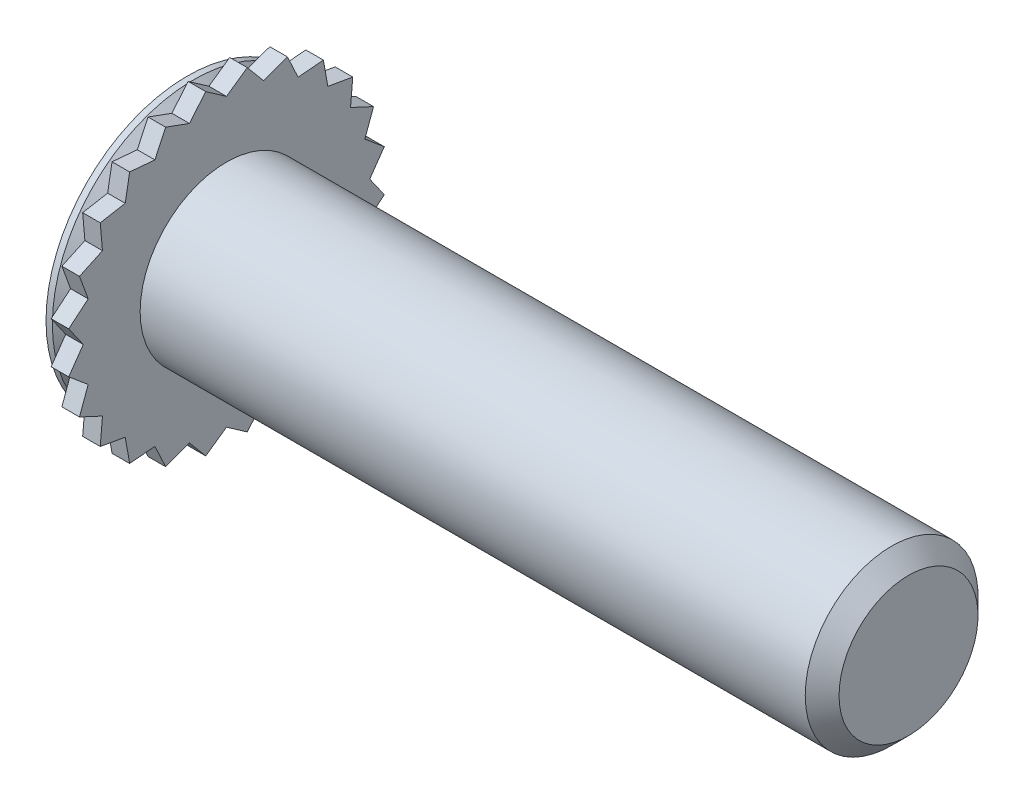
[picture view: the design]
ISO-10303-21;
HEADER;
FILE_DESCRIPTION(('STEP AP214'),'2;1');
FILE_NAME('part.step','',(''),(''),'','','');
FILE_SCHEMA(('AUTOMOTIVE_DESIGN { 1 0 10303 214 1 1 1 1 }'));
ENDSEC;
DATA;
#1=APPLICATION_CONTEXT('core data for automotive mechanical design processes');
#2=APPLICATION_PROTOCOL_DEFINITION('international standard','automotive_design',2000,#1);
#3=PRODUCT_CONTEXT('',#1,'mechanical');
#4=PRODUCT('Part','Part','',(#3));
#5=PRODUCT_RELATED_PRODUCT_CATEGORY('part','',(#4));
#6=PRODUCT_DEFINITION_FORMATION('','',#4);
#7=PRODUCT_DEFINITION_CONTEXT('part definition',#1,'design');
#8=PRODUCT_DEFINITION('design','',#6,#7);
#9=PRODUCT_DEFINITION_SHAPE('','',#8);
#10=(LENGTH_UNIT() NAMED_UNIT(*) SI_UNIT(.MILLI.,.METRE.));
#11=(NAMED_UNIT(*) PLANE_ANGLE_UNIT() SI_UNIT($,.RADIAN.));
#12=(NAMED_UNIT(*) SI_UNIT($,.STERADIAN.) SOLID_ANGLE_UNIT());
#13=UNCERTAINTY_MEASURE_WITH_UNIT(LENGTH_MEASURE(1.E-05),#10,'distance_accuracy_value','');
#14=(GEOMETRIC_REPRESENTATION_CONTEXT(3) GLOBAL_UNCERTAINTY_ASSIGNED_CONTEXT((#13)) GLOBAL_UNIT_ASSIGNED_CONTEXT((#10,
#11,#12)) REPRESENTATION_CONTEXT('',''));
#15=CARTESIAN_POINT('',(0.,0.,0.));
#16=DIRECTION('',(0.,0.,1.));
#17=DIRECTION('',(1.,0.,0.));
#18=AXIS2_PLACEMENT_3D('',#15,#16,#17);
#19=CARTESIAN_POINT('',(1.0922,4.445,0.));
#20=DIRECTION('',(1.,0.,0.));
#21=DIRECTION('',(0.,0.,-1.));
#22=AXIS2_PLACEMENT_3D('',#19,#20,#21);
#23=PLANE('',#22);
#24=DIRECTION('',(0.,0.34225891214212,-0.939605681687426));
#25=VECTOR('',#24,1.);
#26=CARTESIAN_POINT('',(1.0922,4.10664452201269,-1.70102785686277));
#27=LINE('',#26,#25);
#28=CARTESIAN_POINT('',(1.0922,3.86418626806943,-1.03540558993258));
#29=VERTEX_POINT('',#28);
#30=CARTESIAN_POINT('',(1.0922,4.10664452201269,-1.70102785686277));
#31=VERTEX_POINT('',#30);
#32=EDGE_CURVE('E825',#29,#31,#27,.T.);
#33=ORIENTED_EDGE('',*,*,#32,.F.);
#34=DIRECTION('',(0.,-0.766207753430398,-0.642592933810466));
#35=VECTOR('',#34,1.);
#36=CARTESIAN_POINT('',(1.0922,3.86418626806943,-1.03540558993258));
#37=LINE('',#36,#35);
#38=CARTESIAN_POINT('',(1.0922,4.40697240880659,-0.580188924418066));
#39=VERTEX_POINT('',#38);
#40=EDGE_CURVE('E814',#39,#29,#37,.T.);
#41=ORIENTED_EDGE('',*,*,#40,.F.);
#42=DIRECTION('',(0.,0.573784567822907,-0.819006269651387));
#43=VECTOR('',#42,1.);
#44=CARTESIAN_POINT('',(1.0922,4.40697240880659,-0.580188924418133));
#45=LINE('',#44,#43);
#46=CARTESIAN_POINT('',(1.0922,4.0005,0.));
#47=VERTEX_POINT('',#46);
#48=EDGE_CURVE('E198',#47,#39,#45,.T.);
#49=ORIENTED_EDGE('',*,*,#48,.F.);
#50=DIRECTION('',(0.,-0.573784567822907,-0.819006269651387));
#51=VECTOR('',#50,1.);
#52=CARTESIAN_POINT('',(1.0922,4.0005,0.));
#53=LINE('',#52,#51);
#54=CARTESIAN_POINT('',(1.0922,4.40697240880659,0.580188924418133));
#55=VERTEX_POINT('',#54);
#56=EDGE_CURVE('E192',#55,#47,#53,.T.);
#57=ORIENTED_EDGE('',*,*,#56,.F.);
#58=DIRECTION('',(0.,0.766207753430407,-0.642592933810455));
#59=VECTOR('',#58,1.);
#60=CARTESIAN_POINT('',(1.0922,4.40697240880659,0.580188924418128));
#61=LINE('',#60,#59);
#62=CARTESIAN_POINT('',(1.0922,3.86418626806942,1.03540558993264));
#63=VERTEX_POINT('',#62);
#64=EDGE_CURVE('E60',#63,#55,#61,.T.);
#65=ORIENTED_EDGE('',*,*,#64,.F.);
#66=DIRECTION('',(0.,-0.342258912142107,-0.939605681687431));
#67=VECTOR('',#66,1.);
#68=CARTESIAN_POINT('',(1.0922,3.86418626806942,1.03540558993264));
#69=LINE('',#68,#67);
#70=CARTESIAN_POINT('',(1.0922,4.10664452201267,1.70102785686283));
#71=VERTEX_POINT('',#70);
#72=EDGE_CURVE('E177',#71,#63,#69,.T.);
#73=ORIENTED_EDGE('',*,*,#72,.F.);
#74=DIRECTION('',(0.,0.906415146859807,-0.422387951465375));
#75=VECTOR('',#74,1.);
#76=CARTESIAN_POINT('',(1.0922,4.10664452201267,1.70102785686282));
#77=LINE('',#76,#75);
#78=CARTESIAN_POINT('',(1.0922,3.46453462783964,2.00025));
#79=VERTEX_POINT('',#78);
#80=EDGE_CURVE('E77',#79,#71,#77,.T.);
#81=ORIENTED_EDGE('',*,*,#80,.F.);
#82=DIRECTION('',(0.,-0.087408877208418,-0.996172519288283));
#83=VECTOR('',#82,1.);
#84=CARTESIAN_POINT('',(1.0922,3.46453462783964,2.00025));
#85=LINE('',#84,#83);
#86=CARTESIAN_POINT('',(1.0922,3.52645559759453,2.70594455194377));
#87=VERTEX_POINT('',#86);
#88=EDGE_CURVE('E174',#87,#79,#85,.T.);
#89=ORIENTED_EDGE('',*,*,#88,.F.);
#90=DIRECTION('',(0.,0.984851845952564,-0.173397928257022));
#91=VECTOR('',#90,1.);
#92=CARTESIAN_POINT('',(1.0922,3.52645559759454,2.70594455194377));
#93=LINE('',#92,#91);
#94=CARTESIAN_POINT('',(1.0922,2.82878067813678,2.82878067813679));
#95=VERTEX_POINT('',#94);
#96=EDGE_CURVE('E164',#95,#87,#93,.T.);
#97=ORIENTED_EDGE('',*,*,#96,.F.);
#98=DIRECTION('',(0.,0.173397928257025,-0.984851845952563));
#99=VECTOR('',#98,1.);
#100=CARTESIAN_POINT('',(1.0922,2.82878067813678,2.82878067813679));
#101=LINE('',#100,#99);
#102=CARTESIAN_POINT('',(1.0922,2.70594455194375,3.52645559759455));
#103=VERTEX_POINT('',#102);
#104=EDGE_CURVE('E137',#103,#95,#101,.T.);
#105=ORIENTED_EDGE('',*,*,#104,.F.);
#106=DIRECTION('',(0.,0.996172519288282,0.0874088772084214));
#107=VECTOR('',#106,1.);
#108=CARTESIAN_POINT('',(1.0922,2.70594455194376,3.52645559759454));
#109=LINE('',#108,#107);
#110=CARTESIAN_POINT('',(1.0922,2.00024999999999,3.46453462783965));
#111=VERTEX_POINT('',#110);
#112=EDGE_CURVE('E114',#111,#103,#109,.T.);
#113=ORIENTED_EDGE('',*,*,#112,.F.);
#114=DIRECTION('',(0.,0.422387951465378,-0.906415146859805));
#115=VECTOR('',#114,1.);
#116=CARTESIAN_POINT('',(1.0922,2.00024999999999,3.46453462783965));
#117=LINE('',#116,#115);
#118=CARTESIAN_POINT('',(1.0922,1.70102785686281,4.10664452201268));
#119=VERTEX_POINT('',#118);
#120=EDGE_CURVE('E142',#119,#111,#117,.T.);
#121=ORIENTED_EDGE('',*,*,#120,.F.);
#122=DIRECTION('',(0.,0.93960568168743,0.34225891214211));
#123=VECTOR('',#122,1.);
#124=CARTESIAN_POINT('',(1.0922,1.70102785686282,4.10664452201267));
#125=LINE('',#124,#123);
#126=CARTESIAN_POINT('',(1.0922,1.03540558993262,3.86418626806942));
#127=VERTEX_POINT('',#126);
#128=EDGE_CURVE('E1151',#127,#119,#125,.T.);
#129=ORIENTED_EDGE('',*,*,#128,.F.);
#130=DIRECTION('',(0.,0.642592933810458,-0.766207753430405));
#131=VECTOR('',#130,1.);
#132=CARTESIAN_POINT('',(1.0922,1.03540558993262,3.86418626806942));
#133=LINE('',#132,#131);
#134=CARTESIAN_POINT('',(1.0922,0.580188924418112,4.40697240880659));
#135=VERTEX_POINT('',#134);
#136=EDGE_CURVE('E1144',#135,#127,#133,.T.);
#137=ORIENTED_EDGE('',*,*,#136,.F.);
#138=DIRECTION('',(0.,0.819006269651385,0.57378456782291));
#139=VECTOR('',#138,1.);
#140=CARTESIAN_POINT('',(1.0922,0.580188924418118,4.40697240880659));
#141=LINE('',#140,#139);
#142=CARTESIAN_POINT('',(1.0922,0.,4.0005));
#143=VERTEX_POINT('',#142);
#144=EDGE_CURVE('E1133',#143,#135,#141,.T.);
#145=ORIENTED_EDGE('',*,*,#144,.F.);
#146=DIRECTION('',(0.,0.819006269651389,-0.573784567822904));
#147=VECTOR('',#146,1.);
#148=CARTESIAN_POINT('',(1.0922,0.,4.0005));
#149=LINE('',#148,#147);
#150=CARTESIAN_POINT('',(1.0922,-0.580188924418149,4.40697240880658));
#151=VERTEX_POINT('',#150);
#152=EDGE_CURVE('E1126',#151,#143,#149,.T.);
#153=ORIENTED_EDGE('',*,*,#152,.F.);
#154=DIRECTION('',(0.,0.642592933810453,0.76620775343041));
#155=VECTOR('',#154,1.);
#156=CARTESIAN_POINT('',(1.0922,-0.580188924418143,4.40697240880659));
#157=LINE('',#156,#155);
#158=CARTESIAN_POINT('',(1.0922,-1.03540558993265,3.86418626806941));
#159=VERTEX_POINT('',#158);
#160=EDGE_CURVE('E1115',#159,#151,#157,.T.);
#161=ORIENTED_EDGE('',*,*,#160,.F.);
#162=DIRECTION('',(0.,0.939605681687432,-0.342258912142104));
#163=VECTOR('',#162,1.);
#164=CARTESIAN_POINT('',(1.0922,-1.03540558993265,3.86418626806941));
#165=LINE('',#164,#163);
#166=CARTESIAN_POINT('',(1.0922,-1.70102785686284,4.10664452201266));
#167=VERTEX_POINT('',#166);
#168=EDGE_CURVE('E1108',#167,#159,#165,.T.);
#169=ORIENTED_EDGE('',*,*,#168,.F.);
#170=DIRECTION('',(0.,0.422387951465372,0.906415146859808));
#171=VECTOR('',#170,1.);
#172=CARTESIAN_POINT('',(1.0922,-1.70102785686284,4.10664452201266));
#173=LINE('',#172,#171);
#174=CARTESIAN_POINT('',(1.0922,-2.00025000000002,3.46453462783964));
#175=VERTEX_POINT('',#174);
#176=EDGE_CURVE('E1097',#175,#167,#173,.T.);
#177=ORIENTED_EDGE('',*,*,#176,.F.);
#178=DIRECTION('',(0.,0.996172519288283,-0.0874088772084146));
#179=VECTOR('',#178,1.);
#180=CARTESIAN_POINT('',(1.0922,-2.00025000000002,3.46453462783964));
#181=LINE('',#180,#179);
#182=CARTESIAN_POINT('',(1.0922,-2.70594455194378,3.52645559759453));
#183=VERTEX_POINT('',#182);
#184=EDGE_CURVE('E1090',#183,#175,#181,.T.);
#185=ORIENTED_EDGE('',*,*,#184,.F.);
#186=DIRECTION('',(0.,0.173397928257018,0.984851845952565));
#187=VECTOR('',#186,1.);
#188=CARTESIAN_POINT('',(1.0922,-2.70594455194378,3.52645559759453));
#189=LINE('',#188,#187);
#190=CARTESIAN_POINT('',(1.0922,-2.8287806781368,2.82878067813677));
#191=VERTEX_POINT('',#190);
#192=EDGE_CURVE('E1079',#191,#183,#189,.T.);
#193=ORIENTED_EDGE('',*,*,#192,.F.);
#194=DIRECTION('',(0.,0.984851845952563,0.173397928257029));
#195=VECTOR('',#194,1.);
#196=CARTESIAN_POINT('',(1.0922,-2.8287806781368,2.82878067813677));
#197=LINE('',#196,#195);
#198=CARTESIAN_POINT('',(1.0922,-3.52645559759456,2.70594455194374));
#199=VERTEX_POINT('',#198);
#200=EDGE_CURVE('E1072',#199,#191,#197,.T.);
#201=ORIENTED_EDGE('',*,*,#200,.F.);
#202=DIRECTION('',(0.,-0.087408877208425,0.996172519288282));
#203=VECTOR('',#202,1.);
#204=CARTESIAN_POINT('',(1.0922,-3.52645559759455,2.70594455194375));
#205=LINE('',#204,#203);
#206=CARTESIAN_POINT('',(1.0922,-3.46453462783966,2.00024999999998));
#207=VERTEX_POINT('',#206);
#208=EDGE_CURVE('E1061',#207,#199,#205,.T.);
#209=ORIENTED_EDGE('',*,*,#208,.F.);
#210=DIRECTION('',(0.,0.906415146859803,0.422387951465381));
#211=VECTOR('',#210,1.);
#212=CARTESIAN_POINT('',(1.0922,-3.46453462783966,2.00024999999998));
#213=LINE('',#212,#211);
#214=CARTESIAN_POINT('',(1.0922,-4.10664452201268,1.7010278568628));
#215=VERTEX_POINT('',#214);
#216=EDGE_CURVE('E1054',#215,#207,#213,.T.);
#217=ORIENTED_EDGE('',*,*,#216,.F.);
#218=DIRECTION('',(0.,-0.342258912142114,0.939605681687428));
#219=VECTOR('',#218,1.);
#220=CARTESIAN_POINT('',(1.0922,-4.10664452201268,1.7010278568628));
#221=LINE('',#220,#219);
#222=CARTESIAN_POINT('',(1.0922,-3.86418626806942,1.03540558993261));
#223=VERTEX_POINT('',#222);
#224=EDGE_CURVE('E1043',#223,#215,#221,.T.);
#225=ORIENTED_EDGE('',*,*,#224,.F.);
#226=DIRECTION('',(0.,0.766207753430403,0.642592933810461));
#227=VECTOR('',#226,1.);
#228=CARTESIAN_POINT('',(1.0922,-3.86418626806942,1.03540558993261));
#229=LINE('',#228,#227);
#230=CARTESIAN_POINT('',(1.0922,-4.40697240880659,0.580188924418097));
#231=VERTEX_POINT('',#230);
#232=EDGE_CURVE('E1036',#231,#223,#229,.T.);
#233=ORIENTED_EDGE('',*,*,#232,.F.);
#234=DIRECTION('',(0.,-0.573784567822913,0.819006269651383));
#235=VECTOR('',#234,1.);
#236=CARTESIAN_POINT('',(1.0922,-4.40697240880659,0.580188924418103));
#237=LINE('',#236,#235);
#238=CARTESIAN_POINT('',(1.0922,-4.0005,0.));
#239=VERTEX_POINT('',#238);
#240=EDGE_CURVE('E1025',#239,#231,#237,.T.);
#241=ORIENTED_EDGE('',*,*,#240,.F.);
#242=DIRECTION('',(0.,0.573784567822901,0.819006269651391));
#243=VECTOR('',#242,1.);
#244=CARTESIAN_POINT('',(1.0922,-4.0005,0.));
#245=LINE('',#244,#243);
#246=CARTESIAN_POINT('',(1.0922,-4.40697240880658,-0.580188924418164));
#247=VERTEX_POINT('',#246);
#248=EDGE_CURVE('E1018',#247,#239,#245,.T.);
#249=ORIENTED_EDGE('',*,*,#248,.F.);
#250=DIRECTION('',(0.,-0.766207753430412,0.64259293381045));
#251=VECTOR('',#250,1.);
#252=CARTESIAN_POINT('',(1.0922,-4.40697240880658,-0.580188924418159));
#253=LINE('',#252,#251);
#254=CARTESIAN_POINT('',(1.0922,-3.86418626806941,-1.03540558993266));
#255=VERTEX_POINT('',#254);
#256=EDGE_CURVE('E1007',#255,#247,#253,.T.);
#257=ORIENTED_EDGE('',*,*,#256,.F.);
#258=DIRECTION('',(0.,0.342258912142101,0.939605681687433));
#259=VECTOR('',#258,1.);
#260=CARTESIAN_POINT('',(1.0922,-3.86418626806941,-1.03540558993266));
#261=LINE('',#260,#259);
#262=CARTESIAN_POINT('',(1.0922,-4.10664452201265,-1.70102785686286));
#263=VERTEX_POINT('',#262);
#264=EDGE_CURVE('E1000',#263,#255,#261,.T.);
#265=ORIENTED_EDGE('',*,*,#264,.F.);
#266=DIRECTION('',(0.,-0.906415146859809,0.422387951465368));
#267=VECTOR('',#266,1.);
#268=CARTESIAN_POINT('',(1.0922,-4.10664452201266,-1.70102785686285));
#269=LINE('',#268,#267);
#270=CARTESIAN_POINT('',(1.0922,-3.46453462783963,-2.00025000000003));
#271=VERTEX_POINT('',#270);
#272=EDGE_CURVE('E989',#271,#263,#269,.T.);
#273=ORIENTED_EDGE('',*,*,#272,.F.);
#274=DIRECTION('',(0.,0.087408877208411,0.996172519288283));
#275=VECTOR('',#274,1.);
#276=CARTESIAN_POINT('',(1.0922,-3.46453462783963,-2.00025000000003));
#277=LINE('',#276,#275);
#278=CARTESIAN_POINT('',(1.0922,-3.52645559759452,-2.70594455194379));
#279=VERTEX_POINT('',#278);
#280=EDGE_CURVE('E982',#279,#271,#277,.T.);
#281=ORIENTED_EDGE('',*,*,#280,.F.);
#282=DIRECTION('',(0.,-0.984851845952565,0.173397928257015));
#283=VECTOR('',#282,1.);
#284=CARTESIAN_POINT('',(1.0922,-3.52645559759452,-2.70594455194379));
#285=LINE('',#284,#283);
#286=CARTESIAN_POINT('',(1.0922,-2.82878067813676,-2.82878067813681));
#287=VERTEX_POINT('',#286);
#288=EDGE_CURVE('E971',#287,#279,#285,.T.);
#289=ORIENTED_EDGE('',*,*,#288,.F.);
#290=DIRECTION('',(0.,-0.173397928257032,0.984851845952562));
#291=VECTOR('',#290,1.);
#292=CARTESIAN_POINT('',(1.0922,-2.82878067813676,-2.82878067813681));
#293=LINE('',#292,#291);
#294=CARTESIAN_POINT('',(1.0922,-2.70594455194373,-3.52645559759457));
#295=VERTEX_POINT('',#294);
#296=EDGE_CURVE('E964',#295,#287,#293,.T.);
#297=ORIENTED_EDGE('',*,*,#296,.F.);
#298=DIRECTION('',(0.,-0.996172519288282,-0.0874088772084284));
#299=VECTOR('',#298,1.);
#300=CARTESIAN_POINT('',(1.0922,-2.70594455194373,-3.52645559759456));
#301=LINE('',#300,#299);
#302=CARTESIAN_POINT('',(1.0922,-2.00024999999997,-3.46453462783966));
#303=VERTEX_POINT('',#302);
#304=EDGE_CURVE('E953',#303,#295,#301,.T.);
#305=ORIENTED_EDGE('',*,*,#304,.F.);
#306=DIRECTION('',(0.,-0.422387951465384,0.906415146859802));
#307=VECTOR('',#306,1.);
#308=CARTESIAN_POINT('',(1.0922,-2.00024999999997,-3.46453462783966));
#309=LINE('',#308,#307);
#310=CARTESIAN_POINT('',(1.0922,-1.70102785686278,-4.10664452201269));
#311=VERTEX_POINT('',#310);
#312=EDGE_CURVE('E946',#311,#303,#309,.T.);
#313=ORIENTED_EDGE('',*,*,#312,.F.);
#314=DIRECTION('',(0.,-0.939605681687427,-0.342258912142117));
#315=VECTOR('',#314,1.);
#316=CARTESIAN_POINT('',(1.0922,-1.70102785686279,-4.10664452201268));
#317=LINE('',#316,#315);
#318=CARTESIAN_POINT('',(1.0922,-1.0354055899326,-3.86418626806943));
#319=VERTEX_POINT('',#318);
#320=EDGE_CURVE('E935',#319,#311,#317,.T.);
#321=ORIENTED_EDGE('',*,*,#320,.F.);
#322=DIRECTION('',(0.,-0.642592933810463,0.7662077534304));
#323=VECTOR('',#322,1.);
#324=CARTESIAN_POINT('',(1.0922,-1.0354055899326,-3.86418626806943));
#325=LINE('',#324,#323);
#326=CARTESIAN_POINT('',(1.0922,-0.580188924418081,-4.40697240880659));
#327=VERTEX_POINT('',#326);
#328=EDGE_CURVE('E928',#327,#319,#325,.T.);
#329=ORIENTED_EDGE('',*,*,#328,.F.);
#330=DIRECTION('',(0.,-0.819006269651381,-0.573784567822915));
#331=VECTOR('',#330,1.);
#332=CARTESIAN_POINT('',(1.0922,-0.580188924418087,-4.40697240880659));
#333=LINE('',#332,#331);
#334=CARTESIAN_POINT('',(1.0922,0.,-4.0005));
#335=VERTEX_POINT('',#334);
#336=EDGE_CURVE('E917',#335,#327,#333,.T.);
#337=ORIENTED_EDGE('',*,*,#336,.F.);
#338=DIRECTION('',(0.,-0.819006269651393,0.573784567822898));
#339=VECTOR('',#338,1.);
#340=CARTESIAN_POINT('',(1.0922,0.,-4.0005));
#341=LINE('',#340,#339);
#342=CARTESIAN_POINT('',(1.0922,0.58018892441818,-4.40697240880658));
#343=VERTEX_POINT('',#342);
#344=EDGE_CURVE('E910',#343,#335,#341,.T.);
#345=ORIENTED_EDGE('',*,*,#344,.F.);
#346=DIRECTION('',(0.,-0.642592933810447,-0.766207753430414));
#347=VECTOR('',#346,1.);
#348=CARTESIAN_POINT('',(1.0922,0.580188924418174,-4.40697240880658));
#349=LINE('',#348,#347);
#350=CARTESIAN_POINT('',(1.0922,1.03540558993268,-3.86418626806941));
#351=VERTEX_POINT('',#350);
#352=EDGE_CURVE('E899',#351,#343,#349,.T.);
#353=ORIENTED_EDGE('',*,*,#352,.F.);
#354=DIRECTION('',(0.,-0.939605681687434,0.342258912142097));
#355=VECTOR('',#354,1.);
#356=CARTESIAN_POINT('',(1.0922,1.03540558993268,-3.86418626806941));
#357=LINE('',#356,#355);
#358=CARTESIAN_POINT('',(1.0922,1.70102785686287,-4.10664452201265));
#359=VERTEX_POINT('',#358);
#360=EDGE_CURVE('E892',#359,#351,#357,.T.);
#361=ORIENTED_EDGE('',*,*,#360,.F.);
#362=DIRECTION('',(0.,-0.422387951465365,-0.906415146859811));
#363=VECTOR('',#362,1.);
#364=CARTESIAN_POINT('',(1.0922,1.70102785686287,-4.10664452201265));
#365=LINE('',#364,#363);
#366=CARTESIAN_POINT('',(1.0922,2.00025000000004,-3.46453462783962));
#367=VERTEX_POINT('',#366);
#368=EDGE_CURVE('E881',#367,#359,#365,.T.);
#369=ORIENTED_EDGE('',*,*,#368,.F.);
#370=DIRECTION('',(0.,-0.996172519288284,0.0874088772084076));
#371=VECTOR('',#370,1.);
#372=CARTESIAN_POINT('',(1.0922,2.00025000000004,-3.46453462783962));
#373=LINE('',#372,#371);
#374=CARTESIAN_POINT('',(1.0922,2.70594455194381,-3.52645559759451));
#375=VERTEX_POINT('',#374);
#376=EDGE_CURVE('E874',#375,#367,#373,.T.);
#377=ORIENTED_EDGE('',*,*,#376,.F.);
#378=DIRECTION('',(0.,-0.173397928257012,-0.984851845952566));
#379=VECTOR('',#378,1.);
#380=CARTESIAN_POINT('',(1.0922,2.7059445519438,-3.52645559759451));
#381=LINE('',#380,#379);
#382=CARTESIAN_POINT('',(1.0922,2.82878067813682,-2.82878067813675));
#383=VERTEX_POINT('',#382);
#384=EDGE_CURVE('E863',#383,#375,#381,.T.);
#385=ORIENTED_EDGE('',*,*,#384,.F.);
#386=DIRECTION('',(0.,-0.984851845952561,-0.173397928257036));
#387=VECTOR('',#386,1.);
#388=CARTESIAN_POINT('',(1.0922,2.82878067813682,-2.82878067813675));
#389=LINE('',#388,#387);
#390=CARTESIAN_POINT('',(1.0922,3.52645559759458,-2.70594455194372));
#391=VERTEX_POINT('',#390);
#392=EDGE_CURVE('E857',#391,#383,#389,.T.);
#393=ORIENTED_EDGE('',*,*,#392,.F.);
#394=DIRECTION('',(0.,0.0874088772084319,-0.996172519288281));
#395=VECTOR('',#394,1.);
#396=CARTESIAN_POINT('',(1.0922,3.52645559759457,-2.70594455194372));
#397=LINE('',#396,#395);
#398=CARTESIAN_POINT('',(1.0922,3.46453462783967,-2.00024999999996));
#399=VERTEX_POINT('',#398);
#400=EDGE_CURVE('E847',#399,#391,#397,.T.);
#401=ORIENTED_EDGE('',*,*,#400,.F.);
#402=DIRECTION('',(0.,-0.906415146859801,-0.422387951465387));
#403=VECTOR('',#402,1.);
#404=CARTESIAN_POINT('',(1.0922,3.46453462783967,-2.00024999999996));
#405=LINE('',#404,#403);
#406=EDGE_CURVE('E832',#31,#399,#405,.T.);
#407=ORIENTED_EDGE('',*,*,#406,.F.);
#408=EDGE_LOOP('',(#33,#41,#49,#57,#65,#73,#81,#89,#97,#105,#113,#121,#129,#137,#145,#153,#161,
#169,#177,#185,#193,#201,#209,#217,#225,#233,#241,#249,#257,#265,#273,#281,#289,#297,#305,#313,
#321,#329,#337,#345,#353,#361,#369,#377,#385,#393,#401,#407));
#409=FACE_BOUND('',#408,.T.);
#410=CARTESIAN_POINT('',(1.0922,0.,0.));
#411=DIRECTION('',(-1.,0.,0.));
#412=DIRECTION('',(0.,0.,1.));
#413=AXIS2_PLACEMENT_3D('',#410,#411,#412);
#414=CIRCLE('',#413,2.413);
#415=CARTESIAN_POINT('',(1.0922,0.,2.413));
#416=VERTEX_POINT('',#415);
#417=EDGE_CURVE('E11',#416,#416,#414,.T.);
#418=ORIENTED_EDGE('',*,*,#417,.T.);
#419=EDGE_LOOP('',(#418));
#420=FACE_BOUND('',#419,.T.);
#421=ADVANCED_FACE('F33',(#409,#420),#23,.T.);
#422=CARTESIAN_POINT('',(0.,0.,0.));
#423=DIRECTION('',(-1.,0.,0.));
#424=DIRECTION('',(0.,0.,1.));
#425=AXIS2_PLACEMENT_3D('',#422,#423,#424);
#426=CYLINDRICAL_SURFACE('',#425,2.413);
#427=CARTESIAN_POINT('',(19.6697599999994,0.,0.));
#428=DIRECTION('',(-1.,0.,0.));
#429=DIRECTION('',(0.,0.,1.));
#430=AXIS2_PLACEMENT_3D('',#427,#428,#429);
#431=CIRCLE('',#430,2.413);
#432=CARTESIAN_POINT('',(19.6697599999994,0.,2.413));
#433=VERTEX_POINT('',#432);
#434=EDGE_CURVE('E41',#433,#433,#431,.T.);
#435=ORIENTED_EDGE('',*,*,#434,.T.);
#436=EDGE_LOOP('',(#435));
#437=FACE_BOUND('',#436,.T.);
#438=ORIENTED_EDGE('',*,*,#417,.F.);
#439=EDGE_LOOP('',(#438));
#440=FACE_BOUND('',#439,.T.);
#441=ADVANCED_FACE('F232',(#437,#440),#426,.T.);
#442=CARTESIAN_POINT('',(20.1422,0.,0.));
#443=DIRECTION('',(-1.,0.,0.));
#444=DIRECTION('',(0.,0.,1.));
#445=AXIS2_PLACEMENT_3D('',#442,#443,#444);
#446=CONICAL_SURFACE('',#445,1.94056,0.785398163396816);
#447=ORIENTED_EDGE('',*,*,#434,.F.);
#448=EDGE_LOOP('',(#447));
#449=FACE_BOUND('',#448,.T.);
#450=CARTESIAN_POINT('',(20.1422,0.,0.));
#451=DIRECTION('',(-1.,0.,0.));
#452=DIRECTION('',(0.,0.,1.));
#453=AXIS2_PLACEMENT_3D('',#450,#451,#452);
#454=CIRCLE('',#453,1.94056);
#455=CARTESIAN_POINT('',(20.1422,0.,1.94056));
#456=VERTEX_POINT('',#455);
#457=EDGE_CURVE('E227',#456,#456,#454,.T.);
#458=ORIENTED_EDGE('',*,*,#457,.T.);
#459=EDGE_LOOP('',(#458));
#460=FACE_BOUND('',#459,.T.);
#461=ADVANCED_FACE('F235',(#449,#460),#446,.T.);
#462=CARTESIAN_POINT('',(20.1422,1.94056,0.));
#463=DIRECTION('',(1.,0.,0.));
#464=DIRECTION('',(0.,0.,-1.));
#465=AXIS2_PLACEMENT_3D('',#462,#463,#464);
#466=PLANE('',#465);
#467=ORIENTED_EDGE('',*,*,#457,.F.);
#468=EDGE_LOOP('',(#467));
#469=FACE_BOUND('',#468,.T.);
#470=ADVANCED_FACE('F238',(#469),#466,.T.);
#471=CARTESIAN_POINT('',(0.5461,1.6764,0.));
#472=DIRECTION('',(1.,0.,0.));
#473=DIRECTION('',(0.,0.,-1.));
#474=AXIS2_PLACEMENT_3D('',#471,#472,#473);
#475=PLANE('',#474);
#476=CARTESIAN_POINT('',(0.5461,0.,0.));
#477=DIRECTION('',(-1.,0.,0.));
#478=DIRECTION('',(0.,0.,1.));
#479=AXIS2_PLACEMENT_3D('',#476,#477,#478);
#480=CIRCLE('',#479,1.6764);
#481=CARTESIAN_POINT('',(0.5461,0.,1.6764));
#482=VERTEX_POINT('',#481);
#483=EDGE_CURVE('E224',#482,#482,#480,.T.);
#484=ORIENTED_EDGE('',*,*,#483,.T.);
#485=EDGE_LOOP('',(#484));
#486=FACE_BOUND('',#485,.T.);
#487=ADVANCED_FACE('F243',(#486),#475,.F.);
#488=CARTESIAN_POINT('',(0.,0.,0.));
#489=DIRECTION('',(-1.,0.,0.));
#490=DIRECTION('',(0.,0.,1.));
#491=AXIS2_PLACEMENT_3D('',#488,#489,#490);
#492=CONICAL_SURFACE('',#491,2.2225,0.78539816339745);
#493=ORIENTED_EDGE('',*,*,#483,.F.);
#494=EDGE_LOOP('',(#493));
#495=FACE_BOUND('',#494,.T.);
#496=CARTESIAN_POINT('',(0.,0.,0.));
#497=DIRECTION('',(-1.,0.,0.));
#498=DIRECTION('',(0.,0.,1.));
#499=AXIS2_PLACEMENT_3D('',#496,#497,#498);
#500=CIRCLE('',#499,2.2225);
#501=CARTESIAN_POINT('',(0.,0.,2.2225));
#502=VERTEX_POINT('',#501);
#503=EDGE_CURVE('E221',#502,#502,#500,.T.);
#504=ORIENTED_EDGE('',*,*,#503,.T.);
#505=EDGE_LOOP('',(#504));
#506=FACE_BOUND('',#505,.T.);
#507=ADVANCED_FACE('F248',(#495,#506),#492,.F.);
#508=CARTESIAN_POINT('',(0.,2.2225,0.));
#509=DIRECTION('',(-1.,0.,0.));
#510=DIRECTION('',(0.,0.,1.));
#511=AXIS2_PLACEMENT_3D('',#508,#509,#510);
#512=PLANE('',#511);
#513=CARTESIAN_POINT('',(0.,0.,0.));
#514=DIRECTION('',(-1.,0.,0.));
#515=DIRECTION('',(0.,0.,1.));
#516=AXIS2_PLACEMENT_3D('',#513,#514,#515);
#517=CIRCLE('',#516,3.9497);
#518=CARTESIAN_POINT('',(0.,0.,3.9497));
#519=VERTEX_POINT('',#518);
#520=EDGE_CURVE('E218',#519,#519,#517,.T.);
#521=ORIENTED_EDGE('',*,*,#520,.T.);
#522=EDGE_LOOP('',(#521));
#523=FACE_BOUND('',#522,.T.);
#524=ORIENTED_EDGE('',*,*,#503,.F.);
#525=EDGE_LOOP('',(#524));
#526=FACE_BOUND('',#525,.T.);
#527=ADVANCED_FACE('F280',(#523,#526),#512,.T.);
#528=CARTESIAN_POINT('',(0.,0.,0.));
#529=DIRECTION('',(-1.,0.,0.));
#530=DIRECTION('',(0.,0.,1.));
#531=AXIS2_PLACEMENT_3D('',#528,#529,#530);
#532=CYLINDRICAL_SURFACE('',#531,3.9497);
#533=ORIENTED_EDGE('',*,*,#520,.F.);
#534=EDGE_LOOP('',(#533));
#535=FACE_BOUND('',#534,.T.);
#536=CARTESIAN_POINT('',(0.1778,0.,0.));
#537=DIRECTION('',(-1.,0.,0.));
#538=DIRECTION('',(0.,0.,1.));
#539=AXIS2_PLACEMENT_3D('',#536,#537,#538);
#540=CIRCLE('',#539,3.9497);
#541=CARTESIAN_POINT('',(0.1778,0.,3.9497));
#542=VERTEX_POINT('',#541);
#543=EDGE_CURVE('E215',#542,#542,#540,.T.);
#544=ORIENTED_EDGE('',*,*,#543,.T.);
#545=EDGE_LOOP('',(#544));
#546=FACE_BOUND('',#545,.T.);
#547=ADVANCED_FACE('F290',(#535,#546),#532,.T.);
#548=CARTESIAN_POINT('',(0.49149,0.,0.));
#549=DIRECTION('',(-1.,0.,0.));
#550=DIRECTION('',(0.,0.,1.));
#551=AXIS2_PLACEMENT_3D('',#548,#549,#550);
#552=CONICAL_SURFACE('',#551,3.63601,0.785398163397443);
#553=ORIENTED_EDGE('',*,*,#543,.F.);
#554=EDGE_LOOP('',(#553));
#555=FACE_BOUND('',#554,.T.);
#556=CARTESIAN_POINT('',(0.49149,0.,0.));
#557=DIRECTION('',(-1.,0.,0.));
#558=DIRECTION('',(0.,0.,1.));
#559=AXIS2_PLACEMENT_3D('',#556,#557,#558);
#560=CIRCLE('',#559,3.63601);
#561=CARTESIAN_POINT('',(0.49149,0.,3.63601));
#562=VERTEX_POINT('',#561);
#563=EDGE_CURVE('E212',#562,#562,#560,.T.);
#564=ORIENTED_EDGE('',*,*,#563,.T.);
#565=EDGE_LOOP('',(#564));
#566=FACE_BOUND('',#565,.T.);
#567=ADVANCED_FACE('F300',(#555,#566),#552,.T.);
#568=CARTESIAN_POINT('',(0.,0.,0.));
#569=DIRECTION('',(-1.,0.,0.));
#570=DIRECTION('',(0.,0.,1.));
#571=AXIS2_PLACEMENT_3D('',#568,#569,#570);
#572=CYLINDRICAL_SURFACE('',#571,3.63601);
#573=ORIENTED_EDGE('',*,*,#563,.F.);
#574=EDGE_LOOP('',(#573));
#575=FACE_BOUND('',#574,.T.);
#576=CARTESIAN_POINT('',(0.60071,0.,0.));
#577=DIRECTION('',(-1.,0.,0.));
#578=DIRECTION('',(0.,0.,1.));
#579=AXIS2_PLACEMENT_3D('',#576,#577,#578);
#580=CIRCLE('',#579,3.63601);
#581=CARTESIAN_POINT('',(0.60071,0.,3.63601));
#582=VERTEX_POINT('',#581);
#583=EDGE_CURVE('E207',#582,#582,#580,.T.);
#584=ORIENTED_EDGE('',*,*,#583,.T.);
#585=EDGE_LOOP('',(#584));
#586=FACE_BOUND('',#585,.T.);
#587=ADVANCED_FACE('F310',(#575,#586),#572,.T.);
#588=CARTESIAN_POINT('',(0.60071,4.445,0.));
#589=DIRECTION('',(1.,0.,0.));
#590=DIRECTION('',(0.,0.,-1.));
#591=AXIS2_PLACEMENT_3D('',#588,#589,#590);
#592=PLANE('',#591);
#593=ORIENTED_EDGE('',*,*,#583,.F.);
#594=EDGE_LOOP('',(#593));
#595=FACE_BOUND('',#594,.T.);
#596=DIRECTION('',(0.,-0.766207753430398,-0.642592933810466));
#597=VECTOR('',#596,1.);
#598=CARTESIAN_POINT('',(0.60071,3.86418626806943,-1.03540558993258));
#599=LINE('',#598,#597);
#600=CARTESIAN_POINT('',(0.60071,4.40697240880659,-0.580188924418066));
#601=VERTEX_POINT('',#600);
#602=CARTESIAN_POINT('',(0.60071,3.86418626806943,-1.03540558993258));
#603=VERTEX_POINT('',#602);
#604=EDGE_CURVE('E835',#601,#603,#599,.T.);
#605=ORIENTED_EDGE('',*,*,#604,.T.);
#606=DIRECTION('',(0.,0.34225891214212,-0.939605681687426));
#607=VECTOR('',#606,1.);
#608=CARTESIAN_POINT('',(0.60071,4.10664452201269,-1.70102785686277));
#609=LINE('',#608,#607);
#610=CARTESIAN_POINT('',(0.60071,4.10664452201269,-1.70102785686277));
#611=VERTEX_POINT('',#610);
#612=EDGE_CURVE('E838',#603,#611,#609,.T.);
#613=ORIENTED_EDGE('',*,*,#612,.T.);
#614=DIRECTION('',(0.,-0.906415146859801,-0.422387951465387));
#615=VECTOR('',#614,1.);
#616=CARTESIAN_POINT('',(0.60071,3.46453462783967,-2.00024999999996));
#617=LINE('',#616,#615);
#618=CARTESIAN_POINT('',(0.60071,3.46453462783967,-2.00024999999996));
#619=VERTEX_POINT('',#618);
#620=EDGE_CURVE('E843',#611,#619,#617,.T.);
#621=ORIENTED_EDGE('',*,*,#620,.T.);
#622=DIRECTION('',(0.,0.0874088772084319,-0.996172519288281));
#623=VECTOR('',#622,1.);
#624=CARTESIAN_POINT('',(0.60071,3.52645559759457,-2.70594455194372));
#625=LINE('',#624,#623);
#626=CARTESIAN_POINT('',(0.60071,3.52645559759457,-2.70594455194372));
#627=VERTEX_POINT('',#626);
#628=EDGE_CURVE('E846',#619,#627,#625,.T.);
#629=ORIENTED_EDGE('',*,*,#628,.T.);
#630=DIRECTION('',(0.,-0.984851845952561,-0.173397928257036));
#631=VECTOR('',#630,1.);
#632=CARTESIAN_POINT('',(0.60071,2.82878067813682,-2.82878067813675));
#633=LINE('',#632,#631);
#634=CARTESIAN_POINT('',(0.60071,2.82878067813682,-2.82878067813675));
#635=VERTEX_POINT('',#634);
#636=EDGE_CURVE('E859',#627,#635,#633,.T.);
#637=ORIENTED_EDGE('',*,*,#636,.T.);
#638=DIRECTION('',(0.,-0.173397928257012,-0.984851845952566));
#639=VECTOR('',#638,1.);
#640=CARTESIAN_POINT('',(0.60071,2.7059445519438,-3.52645559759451));
#641=LINE('',#640,#639);
#642=CARTESIAN_POINT('',(0.60071,2.7059445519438,-3.52645559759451));
#643=VERTEX_POINT('',#642);
#644=EDGE_CURVE('E862',#635,#643,#641,.T.);
#645=ORIENTED_EDGE('',*,*,#644,.T.);
#646=DIRECTION('',(0.,-0.996172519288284,0.0874088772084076));
#647=VECTOR('',#646,1.);
#648=CARTESIAN_POINT('',(0.60071,2.00025000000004,-3.46453462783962));
#649=LINE('',#648,#647);
#650=CARTESIAN_POINT('',(0.60071,2.00025000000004,-3.46453462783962));
#651=VERTEX_POINT('',#650);
#652=EDGE_CURVE('E877',#643,#651,#649,.T.);
#653=ORIENTED_EDGE('',*,*,#652,.T.);
#654=DIRECTION('',(0.,-0.422387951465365,-0.906415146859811));
#655=VECTOR('',#654,1.);
#656=CARTESIAN_POINT('',(0.60071,1.70102785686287,-4.10664452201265));
#657=LINE('',#656,#655);
#658=CARTESIAN_POINT('',(0.60071,1.70102785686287,-4.10664452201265));
#659=VERTEX_POINT('',#658);
#660=EDGE_CURVE('E880',#651,#659,#657,.T.);
#661=ORIENTED_EDGE('',*,*,#660,.T.);
#662=DIRECTION('',(0.,-0.939605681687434,0.342258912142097));
#663=VECTOR('',#662,1.);
#664=CARTESIAN_POINT('',(0.60071,1.03540558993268,-3.86418626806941));
#665=LINE('',#664,#663);
#666=CARTESIAN_POINT('',(0.60071,1.03540558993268,-3.86418626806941));
#667=VERTEX_POINT('',#666);
#668=EDGE_CURVE('E895',#659,#667,#665,.T.);
#669=ORIENTED_EDGE('',*,*,#668,.T.);
#670=DIRECTION('',(0.,-0.642592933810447,-0.766207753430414));
#671=VECTOR('',#670,1.);
#672=CARTESIAN_POINT('',(0.60071,0.580188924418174,-4.40697240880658));
#673=LINE('',#672,#671);
#674=CARTESIAN_POINT('',(0.60071,0.580188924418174,-4.40697240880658));
#675=VERTEX_POINT('',#674);
#676=EDGE_CURVE('E898',#667,#675,#673,.T.);
#677=ORIENTED_EDGE('',*,*,#676,.T.);
#678=DIRECTION('',(0.,-0.819006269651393,0.573784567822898));
#679=VECTOR('',#678,1.);
#680=CARTESIAN_POINT('',(0.60071,0.,-4.0005));
#681=LINE('',#680,#679);
#682=CARTESIAN_POINT('',(0.60071,0.,-4.0005));
#683=VERTEX_POINT('',#682);
#684=EDGE_CURVE('E913',#675,#683,#681,.T.);
#685=ORIENTED_EDGE('',*,*,#684,.T.);
#686=DIRECTION('',(0.,-0.819006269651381,-0.573784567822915));
#687=VECTOR('',#686,1.);
#688=CARTESIAN_POINT('',(0.60071,-0.580188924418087,-4.40697240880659));
#689=LINE('',#688,#687);
#690=CARTESIAN_POINT('',(0.60071,-0.580188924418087,-4.40697240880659));
#691=VERTEX_POINT('',#690);
#692=EDGE_CURVE('E916',#683,#691,#689,.T.);
#693=ORIENTED_EDGE('',*,*,#692,.T.);
#694=DIRECTION('',(0.,-0.642592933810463,0.7662077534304));
#695=VECTOR('',#694,1.);
#696=CARTESIAN_POINT('',(0.60071,-1.0354055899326,-3.86418626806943));
#697=LINE('',#696,#695);
#698=CARTESIAN_POINT('',(0.60071,-1.0354055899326,-3.86418626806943));
#699=VERTEX_POINT('',#698);
#700=EDGE_CURVE('E931',#691,#699,#697,.T.);
#701=ORIENTED_EDGE('',*,*,#700,.T.);
#702=DIRECTION('',(0.,-0.939605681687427,-0.342258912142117));
#703=VECTOR('',#702,1.);
#704=CARTESIAN_POINT('',(0.60071,-1.70102785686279,-4.10664452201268));
#705=LINE('',#704,#703);
#706=CARTESIAN_POINT('',(0.60071,-1.70102785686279,-4.10664452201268));
#707=VERTEX_POINT('',#706);
#708=EDGE_CURVE('E934',#699,#707,#705,.T.);
#709=ORIENTED_EDGE('',*,*,#708,.T.);
#710=DIRECTION('',(0.,-0.422387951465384,0.906415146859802));
#711=VECTOR('',#710,1.);
#712=CARTESIAN_POINT('',(0.60071,-2.00024999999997,-3.46453462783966));
#713=LINE('',#712,#711);
#714=CARTESIAN_POINT('',(0.60071,-2.00024999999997,-3.46453462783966));
#715=VERTEX_POINT('',#714);
#716=EDGE_CURVE('E949',#707,#715,#713,.T.);
#717=ORIENTED_EDGE('',*,*,#716,.T.);
#718=DIRECTION('',(0.,-0.996172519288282,-0.0874088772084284));
#719=VECTOR('',#718,1.);
#720=CARTESIAN_POINT('',(0.60071,-2.70594455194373,-3.52645559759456));
#721=LINE('',#720,#719);
#722=CARTESIAN_POINT('',(0.60071,-2.70594455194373,-3.52645559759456));
#723=VERTEX_POINT('',#722);
#724=EDGE_CURVE('E952',#715,#723,#721,.T.);
#725=ORIENTED_EDGE('',*,*,#724,.T.);
#726=DIRECTION('',(0.,-0.173397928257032,0.984851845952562));
#727=VECTOR('',#726,1.);
#728=CARTESIAN_POINT('',(0.60071,-2.82878067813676,-2.82878067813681));
#729=LINE('',#728,#727);
#730=CARTESIAN_POINT('',(0.60071,-2.82878067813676,-2.82878067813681));
#731=VERTEX_POINT('',#730);
#732=EDGE_CURVE('E967',#723,#731,#729,.T.);
#733=ORIENTED_EDGE('',*,*,#732,.T.);
#734=DIRECTION('',(0.,-0.984851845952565,0.173397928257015));
#735=VECTOR('',#734,1.);
#736=CARTESIAN_POINT('',(0.60071,-3.52645559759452,-2.70594455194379));
#737=LINE('',#736,#735);
#738=CARTESIAN_POINT('',(0.60071,-3.52645559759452,-2.70594455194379));
#739=VERTEX_POINT('',#738);
#740=EDGE_CURVE('E970',#731,#739,#737,.T.);
#741=ORIENTED_EDGE('',*,*,#740,.T.);
#742=DIRECTION('',(0.,0.087408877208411,0.996172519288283));
#743=VECTOR('',#742,1.);
#744=CARTESIAN_POINT('',(0.60071,-3.46453462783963,-2.00025000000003));
#745=LINE('',#744,#743);
#746=CARTESIAN_POINT('',(0.60071,-3.46453462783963,-2.00025000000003));
#747=VERTEX_POINT('',#746);
#748=EDGE_CURVE('E985',#739,#747,#745,.T.);
#749=ORIENTED_EDGE('',*,*,#748,.T.);
#750=DIRECTION('',(0.,-0.906415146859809,0.422387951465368));
#751=VECTOR('',#750,1.);
#752=CARTESIAN_POINT('',(0.60071,-4.10664452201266,-1.70102785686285));
#753=LINE('',#752,#751);
#754=CARTESIAN_POINT('',(0.60071,-4.10664452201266,-1.70102785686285));
#755=VERTEX_POINT('',#754);
#756=EDGE_CURVE('E988',#747,#755,#753,.T.);
#757=ORIENTED_EDGE('',*,*,#756,.T.);
#758=DIRECTION('',(0.,0.342258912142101,0.939605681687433));
#759=VECTOR('',#758,1.);
#760=CARTESIAN_POINT('',(0.60071,-3.86418626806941,-1.03540558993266));
#761=LINE('',#760,#759);
#762=CARTESIAN_POINT('',(0.60071,-3.86418626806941,-1.03540558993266));
#763=VERTEX_POINT('',#762);
#764=EDGE_CURVE('E1003',#755,#763,#761,.T.);
#765=ORIENTED_EDGE('',*,*,#764,.T.);
#766=DIRECTION('',(0.,-0.766207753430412,0.64259293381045));
#767=VECTOR('',#766,1.);
#768=CARTESIAN_POINT('',(0.60071,-4.40697240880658,-0.580188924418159));
#769=LINE('',#768,#767);
#770=CARTESIAN_POINT('',(0.60071,-4.40697240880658,-0.580188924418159));
#771=VERTEX_POINT('',#770);
#772=EDGE_CURVE('E1006',#763,#771,#769,.T.);
#773=ORIENTED_EDGE('',*,*,#772,.T.);
#774=DIRECTION('',(0.,0.573784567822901,0.819006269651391));
#775=VECTOR('',#774,1.);
#776=CARTESIAN_POINT('',(0.60071,-4.0005,0.));
#777=LINE('',#776,#775);
#778=CARTESIAN_POINT('',(0.60071,-4.0005,0.));
#779=VERTEX_POINT('',#778);
#780=EDGE_CURVE('E1021',#771,#779,#777,.T.);
#781=ORIENTED_EDGE('',*,*,#780,.T.);
#782=DIRECTION('',(0.,-0.573784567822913,0.819006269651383));
#783=VECTOR('',#782,1.);
#784=CARTESIAN_POINT('',(0.60071,-4.40697240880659,0.580188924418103));
#785=LINE('',#784,#783);
#786=CARTESIAN_POINT('',(0.60071,-4.40697240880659,0.580188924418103));
#787=VERTEX_POINT('',#786);
#788=EDGE_CURVE('E1024',#779,#787,#785,.T.);
#789=ORIENTED_EDGE('',*,*,#788,.T.);
#790=DIRECTION('',(0.,0.766207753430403,0.642592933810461));
#791=VECTOR('',#790,1.);
#792=CARTESIAN_POINT('',(0.60071,-3.86418626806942,1.03540558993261));
#793=LINE('',#792,#791);
#794=CARTESIAN_POINT('',(0.60071,-3.86418626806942,1.03540558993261));
#795=VERTEX_POINT('',#794);
#796=EDGE_CURVE('E1039',#787,#795,#793,.T.);
#797=ORIENTED_EDGE('',*,*,#796,.T.);
#798=DIRECTION('',(0.,-0.342258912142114,0.939605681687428));
#799=VECTOR('',#798,1.);
#800=CARTESIAN_POINT('',(0.60071,-4.10664452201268,1.7010278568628));
#801=LINE('',#800,#799);
#802=CARTESIAN_POINT('',(0.60071,-4.10664452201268,1.7010278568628));
#803=VERTEX_POINT('',#802);
#804=EDGE_CURVE('E1042',#795,#803,#801,.T.);
#805=ORIENTED_EDGE('',*,*,#804,.T.);
#806=DIRECTION('',(0.,0.906415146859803,0.422387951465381));
#807=VECTOR('',#806,1.);
#808=CARTESIAN_POINT('',(0.60071,-3.46453462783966,2.00024999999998));
#809=LINE('',#808,#807);
#810=CARTESIAN_POINT('',(0.60071,-3.46453462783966,2.00024999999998));
#811=VERTEX_POINT('',#810);
#812=EDGE_CURVE('E1057',#803,#811,#809,.T.);
#813=ORIENTED_EDGE('',*,*,#812,.T.);
#814=DIRECTION('',(0.,-0.087408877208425,0.996172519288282));
#815=VECTOR('',#814,1.);
#816=CARTESIAN_POINT('',(0.60071,-3.52645559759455,2.70594455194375));
#817=LINE('',#816,#815);
#818=CARTESIAN_POINT('',(0.60071,-3.52645559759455,2.70594455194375));
#819=VERTEX_POINT('',#818);
#820=EDGE_CURVE('E1060',#811,#819,#817,.T.);
#821=ORIENTED_EDGE('',*,*,#820,.T.);
#822=DIRECTION('',(0.,0.984851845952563,0.173397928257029));
#823=VECTOR('',#822,1.);
#824=CARTESIAN_POINT('',(0.60071,-2.8287806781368,2.82878067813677));
#825=LINE('',#824,#823);
#826=CARTESIAN_POINT('',(0.60071,-2.8287806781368,2.82878067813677));
#827=VERTEX_POINT('',#826);
#828=EDGE_CURVE('E1075',#819,#827,#825,.T.);
#829=ORIENTED_EDGE('',*,*,#828,.T.);
#830=DIRECTION('',(0.,0.173397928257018,0.984851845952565));
#831=VECTOR('',#830,1.);
#832=CARTESIAN_POINT('',(0.60071,-2.70594455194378,3.52645559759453));
#833=LINE('',#832,#831);
#834=CARTESIAN_POINT('',(0.60071,-2.70594455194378,3.52645559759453));
#835=VERTEX_POINT('',#834);
#836=EDGE_CURVE('E1078',#827,#835,#833,.T.);
#837=ORIENTED_EDGE('',*,*,#836,.T.);
#838=DIRECTION('',(0.,0.996172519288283,-0.0874088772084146));
#839=VECTOR('',#838,1.);
#840=CARTESIAN_POINT('',(0.60071,-2.00025000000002,3.46453462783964));
#841=LINE('',#840,#839);
#842=CARTESIAN_POINT('',(0.60071,-2.00025000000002,3.46453462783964));
#843=VERTEX_POINT('',#842);
#844=EDGE_CURVE('E1093',#835,#843,#841,.T.);
#845=ORIENTED_EDGE('',*,*,#844,.T.);
#846=DIRECTION('',(0.,0.422387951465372,0.906415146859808));
#847=VECTOR('',#846,1.);
#848=CARTESIAN_POINT('',(0.60071,-1.70102785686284,4.10664452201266));
#849=LINE('',#848,#847);
#850=CARTESIAN_POINT('',(0.60071,-1.70102785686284,4.10664452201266));
#851=VERTEX_POINT('',#850);
#852=EDGE_CURVE('E1096',#843,#851,#849,.T.);
#853=ORIENTED_EDGE('',*,*,#852,.T.);
#854=DIRECTION('',(0.,0.939605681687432,-0.342258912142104));
#855=VECTOR('',#854,1.);
#856=CARTESIAN_POINT('',(0.60071,-1.03540558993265,3.86418626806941));
#857=LINE('',#856,#855);
#858=CARTESIAN_POINT('',(0.60071,-1.03540558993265,3.86418626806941));
#859=VERTEX_POINT('',#858);
#860=EDGE_CURVE('E1111',#851,#859,#857,.T.);
#861=ORIENTED_EDGE('',*,*,#860,.T.);
#862=DIRECTION('',(0.,0.642592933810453,0.76620775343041));
#863=VECTOR('',#862,1.);
#864=CARTESIAN_POINT('',(0.60071,-0.580188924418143,4.40697240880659));
#865=LINE('',#864,#863);
#866=CARTESIAN_POINT('',(0.60071,-0.580188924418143,4.40697240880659));
#867=VERTEX_POINT('',#866);
#868=EDGE_CURVE('E1114',#859,#867,#865,.T.);
#869=ORIENTED_EDGE('',*,*,#868,.T.);
#870=DIRECTION('',(0.,0.819006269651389,-0.573784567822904));
#871=VECTOR('',#870,1.);
#872=CARTESIAN_POINT('',(0.60071,0.,4.0005));
#873=LINE('',#872,#871);
#874=CARTESIAN_POINT('',(0.60071,0.,4.0005));
#875=VERTEX_POINT('',#874);
#876=EDGE_CURVE('E1129',#867,#875,#873,.T.);
#877=ORIENTED_EDGE('',*,*,#876,.T.);
#878=DIRECTION('',(0.,0.819006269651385,0.57378456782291));
#879=VECTOR('',#878,1.);
#880=CARTESIAN_POINT('',(0.60071,0.580188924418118,4.40697240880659));
#881=LINE('',#880,#879);
#882=CARTESIAN_POINT('',(0.60071,0.580188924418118,4.40697240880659));
#883=VERTEX_POINT('',#882);
#884=EDGE_CURVE('E1132',#875,#883,#881,.T.);
#885=ORIENTED_EDGE('',*,*,#884,.T.);
#886=DIRECTION('',(0.,0.642592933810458,-0.766207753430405));
#887=VECTOR('',#886,1.);
#888=CARTESIAN_POINT('',(0.60071,1.03540558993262,3.86418626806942));
#889=LINE('',#888,#887);
#890=CARTESIAN_POINT('',(0.60071,1.03540558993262,3.86418626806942));
#891=VERTEX_POINT('',#890);
#892=EDGE_CURVE('E1147',#883,#891,#889,.T.);
#893=ORIENTED_EDGE('',*,*,#892,.T.);
#894=DIRECTION('',(0.,0.93960568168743,0.34225891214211));
#895=VECTOR('',#894,1.);
#896=CARTESIAN_POINT('',(0.60071,1.70102785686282,4.10664452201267));
#897=LINE('',#896,#895);
#898=CARTESIAN_POINT('',(0.60071,1.70102785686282,4.10664452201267));
#899=VERTEX_POINT('',#898);
#900=EDGE_CURVE('E1150',#891,#899,#897,.T.);
#901=ORIENTED_EDGE('',*,*,#900,.T.);
#902=DIRECTION('',(0.,0.422387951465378,-0.906415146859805));
#903=VECTOR('',#902,1.);
#904=CARTESIAN_POINT('',(0.60071,2.00024999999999,3.46453462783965));
#905=LINE('',#904,#903);
#906=CARTESIAN_POINT('',(0.60071,2.00024999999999,3.46453462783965));
#907=VERTEX_POINT('',#906);
#908=EDGE_CURVE('E154',#899,#907,#905,.T.);
#909=ORIENTED_EDGE('',*,*,#908,.T.);
#910=DIRECTION('',(0.,0.996172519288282,0.0874088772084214));
#911=VECTOR('',#910,1.);
#912=CARTESIAN_POINT('',(0.60071,2.70594455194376,3.52645559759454));
#913=LINE('',#912,#911);
#914=CARTESIAN_POINT('',(0.60071,2.70594455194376,3.52645559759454));
#915=VERTEX_POINT('',#914);
#916=EDGE_CURVE('E133',#907,#915,#913,.T.);
#917=ORIENTED_EDGE('',*,*,#916,.T.);
#918=DIRECTION('',(0.,0.173397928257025,-0.984851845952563));
#919=VECTOR('',#918,1.);
#920=CARTESIAN_POINT('',(0.60071,2.82878067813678,2.82878067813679));
#921=LINE('',#920,#919);
#922=CARTESIAN_POINT('',(0.60071,2.82878067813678,2.82878067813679));
#923=VERTEX_POINT('',#922);
#924=EDGE_CURVE('E160',#915,#923,#921,.T.);
#925=ORIENTED_EDGE('',*,*,#924,.T.);
#926=DIRECTION('',(0.,0.984851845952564,-0.173397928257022));
#927=VECTOR('',#926,1.);
#928=CARTESIAN_POINT('',(0.60071,3.52645559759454,2.70594455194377));
#929=LINE('',#928,#927);
#930=CARTESIAN_POINT('',(0.60071,3.52645559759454,2.70594455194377));
#931=VERTEX_POINT('',#930);
#932=EDGE_CURVE('E163',#923,#931,#929,.T.);
#933=ORIENTED_EDGE('',*,*,#932,.T.);
#934=DIRECTION('',(0.,-0.087408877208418,-0.996172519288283));
#935=VECTOR('',#934,1.);
#936=CARTESIAN_POINT('',(0.60071,3.46453462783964,2.00025));
#937=LINE('',#936,#935);
#938=CARTESIAN_POINT('',(0.60071,3.46453462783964,2.00025));
#939=VERTEX_POINT('',#938);
#940=EDGE_CURVE('E175',#931,#939,#937,.T.);
#941=ORIENTED_EDGE('',*,*,#940,.T.);
#942=DIRECTION('',(0.,0.906415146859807,-0.422387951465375));
#943=VECTOR('',#942,1.);
#944=CARTESIAN_POINT('',(0.60071,4.10664452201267,1.70102785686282));
#945=LINE('',#944,#943);
#946=CARTESIAN_POINT('',(0.60071,4.10664452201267,1.70102785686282));
#947=VERTEX_POINT('',#946);
#948=EDGE_CURVE('E172',#939,#947,#945,.T.);
#949=ORIENTED_EDGE('',*,*,#948,.T.);
#950=DIRECTION('',(0.,-0.342258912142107,-0.939605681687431));
#951=VECTOR('',#950,1.);
#952=CARTESIAN_POINT('',(0.60071,3.86418626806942,1.03540558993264));
#953=LINE('',#952,#951);
#954=CARTESIAN_POINT('',(0.60071,3.86418626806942,1.03540558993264));
#955=VERTEX_POINT('',#954);
#956=EDGE_CURVE('E182',#947,#955,#953,.T.);
#957=ORIENTED_EDGE('',*,*,#956,.T.);
#958=DIRECTION('',(0.,0.766207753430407,-0.642592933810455));
#959=VECTOR('',#958,1.);
#960=CARTESIAN_POINT('',(0.60071,4.40697240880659,0.580188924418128));
#961=LINE('',#960,#959);
#962=CARTESIAN_POINT('',(0.60071,4.40697240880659,0.580188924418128));
#963=VERTEX_POINT('',#962);
#964=EDGE_CURVE('E185',#955,#963,#961,.T.);
#965=ORIENTED_EDGE('',*,*,#964,.T.);
#966=DIRECTION('',(0.,-0.573784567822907,-0.819006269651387));
#967=VECTOR('',#966,1.);
#968=CARTESIAN_POINT('',(0.60071,4.0005,0.));
#969=LINE('',#968,#967);
#970=CARTESIAN_POINT('',(0.60071,4.0005,0.));
#971=VERTEX_POINT('',#970);
#972=EDGE_CURVE('E194',#963,#971,#969,.T.);
#973=ORIENTED_EDGE('',*,*,#972,.T.);
#974=DIRECTION('',(0.,0.573784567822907,-0.819006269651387));
#975=VECTOR('',#974,1.);
#976=CARTESIAN_POINT('',(0.60071,4.40697240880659,-0.580188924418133));
#977=LINE('',#976,#975);
#978=EDGE_CURVE('E197',#971,#601,#977,.T.);
#979=ORIENTED_EDGE('',*,*,#978,.T.);
#980=EDGE_LOOP('',(#605,#613,#621,#629,#637,#645,#653,#661,#669,#677,#685,#693,#701,#709,#717,
#725,#733,#741,#749,#757,#765,#773,#781,#789,#797,#805,#813,#821,#829,#837,#845,#853,#861,#869,
#877,#885,#893,#901,#909,#917,#925,#933,#941,#949,#957,#965,#973,#979));
#981=FACE_BOUND('',#980,.T.);
#982=ADVANCED_FACE('F319',(#595,#981),#592,.F.);
#983=CARTESIAN_POINT('',(0.60071,4.40697240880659,-0.580188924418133));
#984=DIRECTION('',(0.,-0.819006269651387,-0.573784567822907));
#985=DIRECTION('',(0.,0.573784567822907,-0.819006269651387));
#986=AXIS2_PLACEMENT_3D('',#983,#984,#985);
#987=PLANE('',#986);
#988=ORIENTED_EDGE('',*,*,#48,.T.);
#989=DIRECTION('',(1.,0.,0.));
#990=VECTOR('',#989,1.);
#991=CARTESIAN_POINT('',(0.60071,4.40697240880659,-0.580188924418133));
#992=LINE('',#991,#990);
#993=EDGE_CURVE('E204',#601,#39,#992,.T.);
#994=ORIENTED_EDGE('',*,*,#993,.F.);
#995=ORIENTED_EDGE('',*,*,#978,.F.);
#996=DIRECTION('',(1.,0.,0.));
#997=VECTOR('',#996,1.);
#998=CARTESIAN_POINT('',(0.60071,4.0005,0.));
#999=LINE('',#998,#997);
#1000=EDGE_CURVE('E48',#971,#47,#999,.T.);
#1001=ORIENTED_EDGE('',*,*,#1000,.T.);
#1002=EDGE_LOOP('',(#988,#994,#995,#1001));
#1003=FACE_BOUND('',#1002,.T.);
#1004=ADVANCED_FACE('F334',(#1003),#987,.F.);
#1005=CARTESIAN_POINT('',(0.60071,4.0005,0.));
#1006=DIRECTION('',(0.,-0.819006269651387,0.573784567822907));
#1007=DIRECTION('',(0.,-0.573784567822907,-0.819006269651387));
#1008=AXIS2_PLACEMENT_3D('',#1005,#1006,#1007);
#1009=PLANE('',#1008);
#1010=ORIENTED_EDGE('',*,*,#56,.T.);
#1011=ORIENTED_EDGE('',*,*,#1000,.F.);
#1012=ORIENTED_EDGE('',*,*,#972,.F.);
#1013=DIRECTION('',(1.,0.,0.));
#1014=VECTOR('',#1013,1.);
#1015=CARTESIAN_POINT('',(0.60071,4.40697240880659,0.580188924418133));
#1016=LINE('',#1015,#1014);
#1017=EDGE_CURVE('E65',#963,#55,#1016,.T.);
#1018=ORIENTED_EDGE('',*,*,#1017,.T.);
#1019=EDGE_LOOP('',(#1010,#1011,#1012,#1018));
#1020=FACE_BOUND('',#1019,.T.);
#1021=ADVANCED_FACE('F344',(#1020),#1009,.F.);
#1022=CARTESIAN_POINT('',(0.60071,4.40697240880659,0.580188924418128));
#1023=DIRECTION('',(0.,-0.642592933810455,-0.766207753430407));
#1024=DIRECTION('',(0.,0.766207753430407,-0.642592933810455));
#1025=AXIS2_PLACEMENT_3D('',#1022,#1023,#1024);
#1026=PLANE('',#1025);
#1027=ORIENTED_EDGE('',*,*,#64,.T.);
#1028=ORIENTED_EDGE('',*,*,#1017,.F.);
#1029=ORIENTED_EDGE('',*,*,#964,.F.);
#1030=DIRECTION('',(1.,0.,0.));
#1031=VECTOR('',#1030,1.);
#1032=CARTESIAN_POINT('',(0.60071,3.86418626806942,1.03540558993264));
#1033=LINE('',#1032,#1031);
#1034=EDGE_CURVE('E190',#955,#63,#1033,.T.);
#1035=ORIENTED_EDGE('',*,*,#1034,.T.);
#1036=EDGE_LOOP('',(#1027,#1028,#1029,#1035));
#1037=FACE_BOUND('',#1036,.T.);
#1038=ADVANCED_FACE('F354',(#1037),#1026,.F.);
#1039=CARTESIAN_POINT('',(0.60071,3.86418626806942,1.03540558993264));
#1040=DIRECTION('',(0.,-0.939605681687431,0.342258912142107));
#1041=DIRECTION('',(0.,-0.342258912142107,-0.939605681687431));
#1042=AXIS2_PLACEMENT_3D('',#1039,#1040,#1041);
#1043=PLANE('',#1042);
#1044=ORIENTED_EDGE('',*,*,#72,.T.);
#1045=ORIENTED_EDGE('',*,*,#1034,.F.);
#1046=ORIENTED_EDGE('',*,*,#956,.F.);
#1047=DIRECTION('',(1.,0.,0.));
#1048=VECTOR('',#1047,1.);
#1049=CARTESIAN_POINT('',(0.60071,4.10664452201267,1.70102785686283));
#1050=LINE('',#1049,#1048);
#1051=EDGE_CURVE('E94',#947,#71,#1050,.T.);
#1052=ORIENTED_EDGE('',*,*,#1051,.T.);
#1053=EDGE_LOOP('',(#1044,#1045,#1046,#1052));
#1054=FACE_BOUND('',#1053,.T.);
#1055=ADVANCED_FACE('F363',(#1054),#1043,.F.);
#1056=CARTESIAN_POINT('',(0.60071,4.10664452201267,1.70102785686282));
#1057=DIRECTION('',(0.,-0.422387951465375,-0.906415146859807));
#1058=DIRECTION('',(0.,0.906415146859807,-0.422387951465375));
#1059=AXIS2_PLACEMENT_3D('',#1056,#1057,#1058);
#1060=PLANE('',#1059);
#1061=ORIENTED_EDGE('',*,*,#80,.T.);
#1062=ORIENTED_EDGE('',*,*,#1051,.F.);
#1063=ORIENTED_EDGE('',*,*,#948,.F.);
#1064=DIRECTION('',(1.,0.,0.));
#1065=VECTOR('',#1064,1.);
#1066=CARTESIAN_POINT('',(0.60071,3.46453462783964,2.00025));
#1067=LINE('',#1066,#1065);
#1068=EDGE_CURVE('E83',#939,#79,#1067,.T.);
#1069=ORIENTED_EDGE('',*,*,#1068,.T.);
#1070=EDGE_LOOP('',(#1061,#1062,#1063,#1069));
#1071=FACE_BOUND('',#1070,.T.);
#1072=ADVANCED_FACE('F372',(#1071),#1060,.F.);
#1073=CARTESIAN_POINT('',(0.60071,3.46453462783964,2.00025));
#1074=DIRECTION('',(0.,-0.996172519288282,0.087408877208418));
#1075=DIRECTION('',(0.,-0.087408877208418,-0.996172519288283));
#1076=AXIS2_PLACEMENT_3D('',#1073,#1074,#1075);
#1077=PLANE('',#1076);
#1078=ORIENTED_EDGE('',*,*,#88,.T.);
#1079=ORIENTED_EDGE('',*,*,#1068,.F.);
#1080=ORIENTED_EDGE('',*,*,#940,.F.);
#1081=DIRECTION('',(1.,0.,0.));
#1082=VECTOR('',#1081,1.);
#1083=CARTESIAN_POINT('',(0.60071,3.52645559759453,2.70594455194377));
#1084=LINE('',#1083,#1082);
#1085=EDGE_CURVE('E102',#931,#87,#1084,.T.);
#1086=ORIENTED_EDGE('',*,*,#1085,.T.);
#1087=EDGE_LOOP('',(#1078,#1079,#1080,#1086));
#1088=FACE_BOUND('',#1087,.T.);
#1089=ADVANCED_FACE('F382',(#1088),#1077,.F.);
#1090=CARTESIAN_POINT('',(0.60071,3.52645559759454,2.70594455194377));
#1091=DIRECTION('',(0.,-0.173397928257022,-0.984851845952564));
#1092=DIRECTION('',(0.,0.984851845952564,-0.173397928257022));
#1093=AXIS2_PLACEMENT_3D('',#1090,#1091,#1092);
#1094=PLANE('',#1093);
#1095=ORIENTED_EDGE('',*,*,#96,.T.);
#1096=ORIENTED_EDGE('',*,*,#1085,.F.);
#1097=ORIENTED_EDGE('',*,*,#932,.F.);
#1098=DIRECTION('',(1.,0.,0.));
#1099=VECTOR('',#1098,1.);
#1100=CARTESIAN_POINT('',(0.60071,2.82878067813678,2.82878067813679));
#1101=LINE('',#1100,#1099);
#1102=EDGE_CURVE('E168',#923,#95,#1101,.T.);
#1103=ORIENTED_EDGE('',*,*,#1102,.T.);
#1104=EDGE_LOOP('',(#1095,#1096,#1097,#1103));
#1105=FACE_BOUND('',#1104,.T.);
#1106=ADVANCED_FACE('F391',(#1105),#1094,.F.);
#1107=CARTESIAN_POINT('',(0.60071,2.82878067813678,2.82878067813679));
#1108=DIRECTION('',(0.,-0.984851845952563,-0.173397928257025));
#1109=DIRECTION('',(0.,0.173397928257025,-0.984851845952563));
#1110=AXIS2_PLACEMENT_3D('',#1107,#1108,#1109);
#1111=PLANE('',#1110);
#1112=ORIENTED_EDGE('',*,*,#104,.T.);
#1113=ORIENTED_EDGE('',*,*,#1102,.F.);
#1114=ORIENTED_EDGE('',*,*,#924,.F.);
#1115=DIRECTION('',(1.,0.,0.));
#1116=VECTOR('',#1115,1.);
#1117=CARTESIAN_POINT('',(0.60071,2.70594455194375,3.52645559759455));
#1118=LINE('',#1117,#1116);
#1119=EDGE_CURVE('E120',#915,#103,#1118,.T.);
#1120=ORIENTED_EDGE('',*,*,#1119,.T.);
#1121=EDGE_LOOP('',(#1112,#1113,#1114,#1120));
#1122=FACE_BOUND('',#1121,.T.);
#1123=ADVANCED_FACE('F401',(#1122),#1111,.F.);
#1124=CARTESIAN_POINT('',(0.60071,2.70594455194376,3.52645559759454));
#1125=DIRECTION('',(0.,0.0874088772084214,-0.996172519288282));
#1126=DIRECTION('',(0.,0.996172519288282,0.0874088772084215));
#1127=AXIS2_PLACEMENT_3D('',#1124,#1125,#1126);
#1128=PLANE('',#1127);
#1129=ORIENTED_EDGE('',*,*,#112,.T.);
#1130=ORIENTED_EDGE('',*,*,#1119,.F.);
#1131=ORIENTED_EDGE('',*,*,#916,.F.);
#1132=DIRECTION('',(1.,0.,0.));
#1133=VECTOR('',#1132,1.);
#1134=CARTESIAN_POINT('',(0.60071,2.00024999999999,3.46453462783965));
#1135=LINE('',#1134,#1133);
#1136=EDGE_CURVE('E130',#907,#111,#1135,.T.);
#1137=ORIENTED_EDGE('',*,*,#1136,.T.);
#1138=EDGE_LOOP('',(#1129,#1130,#1131,#1137));
#1139=FACE_BOUND('',#1138,.T.);
#1140=ADVANCED_FACE('F132',(#1139),#1128,.F.);
#1141=CARTESIAN_POINT('',(0.60071,2.00024999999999,3.46453462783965));
#1142=DIRECTION('',(0.,-0.906415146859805,-0.422387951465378));
#1143=DIRECTION('',(0.,0.422387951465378,-0.906415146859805));
#1144=AXIS2_PLACEMENT_3D('',#1141,#1142,#1143);
#1145=PLANE('',#1144);
#1146=ORIENTED_EDGE('',*,*,#120,.T.);
#1147=ORIENTED_EDGE('',*,*,#1136,.F.);
#1148=ORIENTED_EDGE('',*,*,#908,.F.);
#1149=DIRECTION('',(1.,0.,0.));
#1150=VECTOR('',#1149,1.);
#1151=CARTESIAN_POINT('',(0.60071,1.70102785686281,4.10664452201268));
#1152=LINE('',#1151,#1150);
#1153=EDGE_CURVE('E138',#899,#119,#1152,.T.);
#1154=ORIENTED_EDGE('',*,*,#1153,.T.);
#1155=EDGE_LOOP('',(#1146,#1147,#1148,#1154));
#1156=FACE_BOUND('',#1155,.T.);
#1157=ADVANCED_FACE('F143',(#1156),#1145,.F.);
#1158=CARTESIAN_POINT('',(0.60071,1.70102785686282,4.10664452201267));
#1159=DIRECTION('',(0.,0.34225891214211,-0.939605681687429));
#1160=DIRECTION('',(0.,0.93960568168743,0.34225891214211));
#1161=AXIS2_PLACEMENT_3D('',#1158,#1159,#1160);
#1162=PLANE('',#1161);
#1163=ORIENTED_EDGE('',*,*,#128,.T.);
#1164=ORIENTED_EDGE('',*,*,#1153,.F.);
#1165=ORIENTED_EDGE('',*,*,#900,.F.);
#1166=DIRECTION('',(1.,0.,0.));
#1167=VECTOR('',#1166,1.);
#1168=CARTESIAN_POINT('',(0.60071,1.03540558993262,3.86418626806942));
#1169=LINE('',#1168,#1167);
#1170=EDGE_CURVE('E147',#891,#127,#1169,.T.);
#1171=ORIENTED_EDGE('',*,*,#1170,.T.);
#1172=EDGE_LOOP('',(#1163,#1164,#1165,#1171));
#1173=FACE_BOUND('',#1172,.T.);
#1174=ADVANCED_FACE('F427',(#1173),#1162,.F.);
#1175=CARTESIAN_POINT('',(0.60071,1.03540558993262,3.86418626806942));
#1176=DIRECTION('',(0.,-0.766207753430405,-0.642592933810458));
#1177=DIRECTION('',(0.,0.642592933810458,-0.766207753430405));
#1178=AXIS2_PLACEMENT_3D('',#1175,#1176,#1177);
#1179=PLANE('',#1178);
#1180=ORIENTED_EDGE('',*,*,#136,.T.);
#1181=ORIENTED_EDGE('',*,*,#1170,.F.);
#1182=ORIENTED_EDGE('',*,*,#892,.F.);
#1183=DIRECTION('',(1.,0.,0.));
#1184=VECTOR('',#1183,1.);
#1185=CARTESIAN_POINT('',(0.60071,0.580188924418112,4.40697240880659));
#1186=LINE('',#1185,#1184);
#1187=EDGE_CURVE('E1154',#883,#135,#1186,.T.);
#1188=ORIENTED_EDGE('',*,*,#1187,.T.);
#1189=EDGE_LOOP('',(#1180,#1181,#1182,#1188));
#1190=FACE_BOUND('',#1189,.T.);
#1191=ADVANCED_FACE('F436',(#1190),#1179,.F.);
#1192=CARTESIAN_POINT('',(0.60071,0.580188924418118,4.40697240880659));
#1193=DIRECTION('',(0.,0.57378456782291,-0.819006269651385));
#1194=DIRECTION('',(0.,0.819006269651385,0.57378456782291));
#1195=AXIS2_PLACEMENT_3D('',#1192,#1193,#1194);
#1196=PLANE('',#1195);
#1197=ORIENTED_EDGE('',*,*,#144,.T.);
#1198=ORIENTED_EDGE('',*,*,#1187,.F.);
#1199=ORIENTED_EDGE('',*,*,#884,.F.);
#1200=DIRECTION('',(1.,0.,0.));
#1201=VECTOR('',#1200,1.);
#1202=CARTESIAN_POINT('',(0.60071,0.,4.0005));
#1203=LINE('',#1202,#1201);
#1204=EDGE_CURVE('E1141',#875,#143,#1203,.T.);
#1205=ORIENTED_EDGE('',*,*,#1204,.T.);
#1206=EDGE_LOOP('',(#1197,#1198,#1199,#1205));
#1207=FACE_BOUND('',#1206,.T.);
#1208=ADVANCED_FACE('F446',(#1207),#1196,.F.);
#1209=CARTESIAN_POINT('',(0.60071,0.,4.0005));
#1210=DIRECTION('',(0.,-0.573784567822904,-0.819006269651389));
#1211=DIRECTION('',(0.,0.819006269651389,-0.573784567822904));
#1212=AXIS2_PLACEMENT_3D('',#1209,#1210,#1211);
#1213=PLANE('',#1212);
#1214=ORIENTED_EDGE('',*,*,#152,.T.);
#1215=ORIENTED_EDGE('',*,*,#1204,.F.);
#1216=ORIENTED_EDGE('',*,*,#876,.F.);
#1217=DIRECTION('',(1.,0.,0.));
#1218=VECTOR('',#1217,1.);
#1219=CARTESIAN_POINT('',(0.60071,-0.580188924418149,4.40697240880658));
#1220=LINE('',#1219,#1218);
#1221=EDGE_CURVE('E1136',#867,#151,#1220,.T.);
#1222=ORIENTED_EDGE('',*,*,#1221,.T.);
#1223=EDGE_LOOP('',(#1214,#1215,#1216,#1222));
#1224=FACE_BOUND('',#1223,.T.);
#1225=ADVANCED_FACE('F456',(#1224),#1213,.F.);
#1226=CARTESIAN_POINT('',(0.60071,-0.580188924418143,4.40697240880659));
#1227=DIRECTION('',(0.,0.766207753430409,-0.642592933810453));
#1228=DIRECTION('',(0.,0.642592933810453,0.766207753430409));
#1229=AXIS2_PLACEMENT_3D('',#1226,#1227,#1228);
#1230=PLANE('',#1229);
#1231=ORIENTED_EDGE('',*,*,#160,.T.);
#1232=ORIENTED_EDGE('',*,*,#1221,.F.);
#1233=ORIENTED_EDGE('',*,*,#868,.F.);
#1234=DIRECTION('',(1.,0.,0.));
#1235=VECTOR('',#1234,1.);
#1236=CARTESIAN_POINT('',(0.60071,-1.03540558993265,3.86418626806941));
#1237=LINE('',#1236,#1235);
#1238=EDGE_CURVE('E1123',#859,#159,#1237,.T.);
#1239=ORIENTED_EDGE('',*,*,#1238,.T.);
#1240=EDGE_LOOP('',(#1231,#1232,#1233,#1239));
#1241=FACE_BOUND('',#1240,.T.);
#1242=ADVANCED_FACE('F466',(#1241),#1230,.F.);
#1243=CARTESIAN_POINT('',(0.60071,-1.03540558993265,3.86418626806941));
#1244=DIRECTION('',(0.,-0.342258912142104,-0.939605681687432));
#1245=DIRECTION('',(0.,0.939605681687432,-0.342258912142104));
#1246=AXIS2_PLACEMENT_3D('',#1243,#1244,#1245);
#1247=PLANE('',#1246);
#1248=ORIENTED_EDGE('',*,*,#168,.T.);
#1249=ORIENTED_EDGE('',*,*,#1238,.F.);
#1250=ORIENTED_EDGE('',*,*,#860,.F.);
#1251=DIRECTION('',(1.,0.,0.));
#1252=VECTOR('',#1251,1.);
#1253=CARTESIAN_POINT('',(0.60071,-1.70102785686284,4.10664452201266));
#1254=LINE('',#1253,#1252);
#1255=EDGE_CURVE('E1118',#851,#167,#1254,.T.);
#1256=ORIENTED_EDGE('',*,*,#1255,.T.);
#1257=EDGE_LOOP('',(#1248,#1249,#1250,#1256));
#1258=FACE_BOUND('',#1257,.T.);
#1259=ADVANCED_FACE('F476',(#1258),#1247,.F.);
#1260=CARTESIAN_POINT('',(0.60071,-1.70102785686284,4.10664452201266));
#1261=DIRECTION('',(0.,0.906415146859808,-0.422387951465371));
#1262=DIRECTION('',(0.,0.422387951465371,0.906415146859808));
#1263=AXIS2_PLACEMENT_3D('',#1260,#1261,#1262);
#1264=PLANE('',#1263);
#1265=ORIENTED_EDGE('',*,*,#176,.T.);
#1266=ORIENTED_EDGE('',*,*,#1255,.F.);
#1267=ORIENTED_EDGE('',*,*,#852,.F.);
#1268=DIRECTION('',(1.,0.,0.));
#1269=VECTOR('',#1268,1.);
#1270=CARTESIAN_POINT('',(0.60071,-2.00025000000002,3.46453462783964));
#1271=LINE('',#1270,#1269);
#1272=EDGE_CURVE('E1105',#843,#175,#1271,.T.);
#1273=ORIENTED_EDGE('',*,*,#1272,.T.);
#1274=EDGE_LOOP('',(#1265,#1266,#1267,#1273));
#1275=FACE_BOUND('',#1274,.T.);
#1276=ADVANCED_FACE('F486',(#1275),#1264,.F.);
#1277=CARTESIAN_POINT('',(0.60071,-2.00025000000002,3.46453462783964));
#1278=DIRECTION('',(0.,-0.0874088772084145,-0.996172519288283));
#1279=DIRECTION('',(0.,0.996172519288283,-0.0874088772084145));
#1280=AXIS2_PLACEMENT_3D('',#1277,#1278,#1279);
#1281=PLANE('',#1280);
#1282=ORIENTED_EDGE('',*,*,#184,.T.);
#1283=ORIENTED_EDGE('',*,*,#1272,.F.);
#1284=ORIENTED_EDGE('',*,*,#844,.F.);
#1285=DIRECTION('',(1.,0.,0.));
#1286=VECTOR('',#1285,1.);
#1287=CARTESIAN_POINT('',(0.60071,-2.70594455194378,3.52645559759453));
#1288=LINE('',#1287,#1286);
#1289=EDGE_CURVE('E1100',#835,#183,#1288,.T.);
#1290=ORIENTED_EDGE('',*,*,#1289,.T.);
#1291=EDGE_LOOP('',(#1282,#1283,#1284,#1290));
#1292=FACE_BOUND('',#1291,.T.);
#1293=ADVANCED_FACE('F496',(#1292),#1281,.F.);
#1294=CARTESIAN_POINT('',(0.60071,-2.70594455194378,3.52645559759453));
#1295=DIRECTION('',(0.,0.984851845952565,-0.173397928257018));
#1296=DIRECTION('',(0.,0.173397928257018,0.984851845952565));
#1297=AXIS2_PLACEMENT_3D('',#1294,#1295,#1296);
#1298=PLANE('',#1297);
#1299=ORIENTED_EDGE('',*,*,#192,.T.);
#1300=ORIENTED_EDGE('',*,*,#1289,.F.);
#1301=ORIENTED_EDGE('',*,*,#836,.F.);
#1302=DIRECTION('',(1.,0.,0.));
#1303=VECTOR('',#1302,1.);
#1304=CARTESIAN_POINT('',(0.60071,-2.8287806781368,2.82878067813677));
#1305=LINE('',#1304,#1303);
#1306=EDGE_CURVE('E1087',#827,#191,#1305,.T.);
#1307=ORIENTED_EDGE('',*,*,#1306,.T.);
#1308=EDGE_LOOP('',(#1299,#1300,#1301,#1307));
#1309=FACE_BOUND('',#1308,.T.);
#1310=ADVANCED_FACE('F506',(#1309),#1298,.F.);
#1311=CARTESIAN_POINT('',(0.60071,-2.8287806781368,2.82878067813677));
#1312=DIRECTION('',(0.,0.173397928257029,-0.984851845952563));
#1313=DIRECTION('',(0.,0.984851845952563,0.173397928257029));
#1314=AXIS2_PLACEMENT_3D('',#1311,#1312,#1313);
#1315=PLANE('',#1314);
#1316=ORIENTED_EDGE('',*,*,#200,.T.);
#1317=ORIENTED_EDGE('',*,*,#1306,.F.);
#1318=ORIENTED_EDGE('',*,*,#828,.F.);
#1319=DIRECTION('',(1.,0.,0.));
#1320=VECTOR('',#1319,1.);
#1321=CARTESIAN_POINT('',(0.60071,-3.52645559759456,2.70594455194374));
#1322=LINE('',#1321,#1320);
#1323=EDGE_CURVE('E1082',#819,#199,#1322,.T.);
#1324=ORIENTED_EDGE('',*,*,#1323,.T.);
#1325=EDGE_LOOP('',(#1316,#1317,#1318,#1324));
#1326=FACE_BOUND('',#1325,.T.);
#1327=ADVANCED_FACE('F516',(#1326),#1315,.F.);
#1328=CARTESIAN_POINT('',(0.60071,-3.52645559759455,2.70594455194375));
#1329=DIRECTION('',(0.,0.996172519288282,0.087408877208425));
#1330=DIRECTION('',(0.,-0.087408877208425,0.996172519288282));
#1331=AXIS2_PLACEMENT_3D('',#1328,#1329,#1330);
#1332=PLANE('',#1331);
#1333=ORIENTED_EDGE('',*,*,#208,.T.);
#1334=ORIENTED_EDGE('',*,*,#1323,.F.);
#1335=ORIENTED_EDGE('',*,*,#820,.F.);
#1336=DIRECTION('',(1.,0.,0.));
#1337=VECTOR('',#1336,1.);
#1338=CARTESIAN_POINT('',(0.60071,-3.46453462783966,2.00024999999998));
#1339=LINE('',#1338,#1337);
#1340=EDGE_CURVE('E1069',#811,#207,#1339,.T.);
#1341=ORIENTED_EDGE('',*,*,#1340,.T.);
#1342=EDGE_LOOP('',(#1333,#1334,#1335,#1341));
#1343=FACE_BOUND('',#1342,.T.);
#1344=ADVANCED_FACE('F526',(#1343),#1332,.F.);
#1345=CARTESIAN_POINT('',(0.60071,-3.46453462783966,2.00024999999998));
#1346=DIRECTION('',(0.,0.422387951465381,-0.906415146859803));
#1347=DIRECTION('',(0.,0.906415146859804,0.422387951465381));
#1348=AXIS2_PLACEMENT_3D('',#1345,#1346,#1347);
#1349=PLANE('',#1348);
#1350=ORIENTED_EDGE('',*,*,#216,.T.);
#1351=ORIENTED_EDGE('',*,*,#1340,.F.);
#1352=ORIENTED_EDGE('',*,*,#812,.F.);
#1353=DIRECTION('',(1.,0.,0.));
#1354=VECTOR('',#1353,1.);
#1355=CARTESIAN_POINT('',(0.60071,-4.10664452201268,1.7010278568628));
#1356=LINE('',#1355,#1354);
#1357=EDGE_CURVE('E1064',#803,#215,#1356,.T.);
#1358=ORIENTED_EDGE('',*,*,#1357,.T.);
#1359=EDGE_LOOP('',(#1350,#1351,#1352,#1358));
#1360=FACE_BOUND('',#1359,.T.);
#1361=ADVANCED_FACE('F536',(#1360),#1349,.F.);
#1362=CARTESIAN_POINT('',(0.60071,-4.10664452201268,1.7010278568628));
#1363=DIRECTION('',(0.,0.939605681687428,0.342258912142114));
#1364=DIRECTION('',(0.,-0.342258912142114,0.939605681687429));
#1365=AXIS2_PLACEMENT_3D('',#1362,#1363,#1364);
#1366=PLANE('',#1365);
#1367=ORIENTED_EDGE('',*,*,#224,.T.);
#1368=ORIENTED_EDGE('',*,*,#1357,.F.);
#1369=ORIENTED_EDGE('',*,*,#804,.F.);
#1370=DIRECTION('',(1.,0.,0.));
#1371=VECTOR('',#1370,1.);
#1372=CARTESIAN_POINT('',(0.60071,-3.86418626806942,1.03540558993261));
#1373=LINE('',#1372,#1371);
#1374=EDGE_CURVE('E1051',#795,#223,#1373,.T.);
#1375=ORIENTED_EDGE('',*,*,#1374,.T.);
#1376=EDGE_LOOP('',(#1367,#1368,#1369,#1375));
#1377=FACE_BOUND('',#1376,.T.);
#1378=ADVANCED_FACE('F546',(#1377),#1366,.F.);
#1379=CARTESIAN_POINT('',(0.60071,-3.86418626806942,1.03540558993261));
#1380=DIRECTION('',(0.,0.642592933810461,-0.766207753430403));
#1381=DIRECTION('',(0.,0.766207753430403,0.642592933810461));
#1382=AXIS2_PLACEMENT_3D('',#1379,#1380,#1381);
#1383=PLANE('',#1382);
#1384=ORIENTED_EDGE('',*,*,#232,.T.);
#1385=ORIENTED_EDGE('',*,*,#1374,.F.);
#1386=ORIENTED_EDGE('',*,*,#796,.F.);
#1387=DIRECTION('',(1.,0.,0.));
#1388=VECTOR('',#1387,1.);
#1389=CARTESIAN_POINT('',(0.60071,-4.40697240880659,0.580188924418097));
#1390=LINE('',#1389,#1388);
#1391=EDGE_CURVE('E1046',#787,#231,#1390,.T.);
#1392=ORIENTED_EDGE('',*,*,#1391,.T.);
#1393=EDGE_LOOP('',(#1384,#1385,#1386,#1392));
#1394=FACE_BOUND('',#1393,.T.);
#1395=ADVANCED_FACE('F556',(#1394),#1383,.F.);
#1396=CARTESIAN_POINT('',(0.60071,-4.40697240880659,0.580188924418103));
#1397=DIRECTION('',(0.,0.819006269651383,0.573784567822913));
#1398=DIRECTION('',(0.,-0.573784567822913,0.819006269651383));
#1399=AXIS2_PLACEMENT_3D('',#1396,#1397,#1398);
#1400=PLANE('',#1399);
#1401=ORIENTED_EDGE('',*,*,#240,.T.);
#1402=ORIENTED_EDGE('',*,*,#1391,.F.);
#1403=ORIENTED_EDGE('',*,*,#788,.F.);
#1404=DIRECTION('',(1.,0.,0.));
#1405=VECTOR('',#1404,1.);
#1406=CARTESIAN_POINT('',(0.60071,-4.0005,0.));
#1407=LINE('',#1406,#1405);
#1408=EDGE_CURVE('E1033',#779,#239,#1407,.T.);
#1409=ORIENTED_EDGE('',*,*,#1408,.T.);
#1410=EDGE_LOOP('',(#1401,#1402,#1403,#1409));
#1411=FACE_BOUND('',#1410,.T.);
#1412=ADVANCED_FACE('F566',(#1411),#1400,.F.);
#1413=CARTESIAN_POINT('',(0.60071,-4.0005,0.));
#1414=DIRECTION('',(0.,0.819006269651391,-0.573784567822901));
#1415=DIRECTION('',(0.,0.573784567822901,0.819006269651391));
#1416=AXIS2_PLACEMENT_3D('',#1413,#1414,#1415);
#1417=PLANE('',#1416);
#1418=ORIENTED_EDGE('',*,*,#248,.T.);
#1419=ORIENTED_EDGE('',*,*,#1408,.F.);
#1420=ORIENTED_EDGE('',*,*,#780,.F.);
#1421=DIRECTION('',(1.,0.,0.));
#1422=VECTOR('',#1421,1.);
#1423=CARTESIAN_POINT('',(0.60071,-4.40697240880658,-0.580188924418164));
#1424=LINE('',#1423,#1422);
#1425=EDGE_CURVE('E1028',#771,#247,#1424,.T.);
#1426=ORIENTED_EDGE('',*,*,#1425,.T.);
#1427=EDGE_LOOP('',(#1418,#1419,#1420,#1426));
#1428=FACE_BOUND('',#1427,.T.);
#1429=ADVANCED_FACE('F576',(#1428),#1417,.F.);
#1430=CARTESIAN_POINT('',(0.60071,-4.40697240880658,-0.580188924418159));
#1431=DIRECTION('',(0.,0.64259293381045,0.766207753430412));
#1432=DIRECTION('',(0.,-0.766207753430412,0.64259293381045));
#1433=AXIS2_PLACEMENT_3D('',#1430,#1431,#1432);
#1434=PLANE('',#1433);
#1435=ORIENTED_EDGE('',*,*,#256,.T.);
#1436=ORIENTED_EDGE('',*,*,#1425,.F.);
#1437=ORIENTED_EDGE('',*,*,#772,.F.);
#1438=DIRECTION('',(1.,0.,0.));
#1439=VECTOR('',#1438,1.);
#1440=CARTESIAN_POINT('',(0.60071,-3.86418626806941,-1.03540558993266));
#1441=LINE('',#1440,#1439);
#1442=EDGE_CURVE('E1015',#763,#255,#1441,.T.);
#1443=ORIENTED_EDGE('',*,*,#1442,.T.);
#1444=EDGE_LOOP('',(#1435,#1436,#1437,#1443));
#1445=FACE_BOUND('',#1444,.T.);
#1446=ADVANCED_FACE('F586',(#1445),#1434,.F.);
#1447=CARTESIAN_POINT('',(0.60071,-3.86418626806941,-1.03540558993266));
#1448=DIRECTION('',(0.,0.939605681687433,-0.342258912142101));
#1449=DIRECTION('',(0.,0.342258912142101,0.939605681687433));
#1450=AXIS2_PLACEMENT_3D('',#1447,#1448,#1449);
#1451=PLANE('',#1450);
#1452=ORIENTED_EDGE('',*,*,#264,.T.);
#1453=ORIENTED_EDGE('',*,*,#1442,.F.);
#1454=ORIENTED_EDGE('',*,*,#764,.F.);
#1455=DIRECTION('',(1.,0.,0.));
#1456=VECTOR('',#1455,1.);
#1457=CARTESIAN_POINT('',(0.60071,-4.10664452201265,-1.70102785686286));
#1458=LINE('',#1457,#1456);
#1459=EDGE_CURVE('E1010',#755,#263,#1458,.T.);
#1460=ORIENTED_EDGE('',*,*,#1459,.T.);
#1461=EDGE_LOOP('',(#1452,#1453,#1454,#1460));
#1462=FACE_BOUND('',#1461,.T.);
#1463=ADVANCED_FACE('F596',(#1462),#1451,.F.);
#1464=CARTESIAN_POINT('',(0.60071,-4.10664452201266,-1.70102785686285));
#1465=DIRECTION('',(0.,0.422387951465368,0.906415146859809));
#1466=DIRECTION('',(0.,-0.906415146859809,0.422387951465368));
#1467=AXIS2_PLACEMENT_3D('',#1464,#1465,#1466);
#1468=PLANE('',#1467);
#1469=ORIENTED_EDGE('',*,*,#272,.T.);
#1470=ORIENTED_EDGE('',*,*,#1459,.F.);
#1471=ORIENTED_EDGE('',*,*,#756,.F.);
#1472=DIRECTION('',(1.,0.,0.));
#1473=VECTOR('',#1472,1.);
#1474=CARTESIAN_POINT('',(0.60071,-3.46453462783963,-2.00025000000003));
#1475=LINE('',#1474,#1473);
#1476=EDGE_CURVE('E997',#747,#271,#1475,.T.);
#1477=ORIENTED_EDGE('',*,*,#1476,.T.);
#1478=EDGE_LOOP('',(#1469,#1470,#1471,#1477));
#1479=FACE_BOUND('',#1478,.T.);
#1480=ADVANCED_FACE('F606',(#1479),#1468,.F.);
#1481=CARTESIAN_POINT('',(0.60071,-3.46453462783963,-2.00025000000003));
#1482=DIRECTION('',(0.,0.996172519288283,-0.087408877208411));
#1483=DIRECTION('',(0.,0.087408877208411,0.996172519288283));
#1484=AXIS2_PLACEMENT_3D('',#1481,#1482,#1483);
#1485=PLANE('',#1484);
#1486=ORIENTED_EDGE('',*,*,#280,.T.);
#1487=ORIENTED_EDGE('',*,*,#1476,.F.);
#1488=ORIENTED_EDGE('',*,*,#748,.F.);
#1489=DIRECTION('',(1.,0.,0.));
#1490=VECTOR('',#1489,1.);
#1491=CARTESIAN_POINT('',(0.60071,-3.52645559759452,-2.70594455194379));
#1492=LINE('',#1491,#1490);
#1493=EDGE_CURVE('E992',#739,#279,#1492,.T.);
#1494=ORIENTED_EDGE('',*,*,#1493,.T.);
#1495=EDGE_LOOP('',(#1486,#1487,#1488,#1494));
#1496=FACE_BOUND('',#1495,.T.);
#1497=ADVANCED_FACE('F616',(#1496),#1485,.F.);
#1498=CARTESIAN_POINT('',(0.60071,-3.52645559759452,-2.70594455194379));
#1499=DIRECTION('',(0.,0.173397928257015,0.984851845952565));
#1500=DIRECTION('',(0.,-0.984851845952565,0.173397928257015));
#1501=AXIS2_PLACEMENT_3D('',#1498,#1499,#1500);
#1502=PLANE('',#1501);
#1503=ORIENTED_EDGE('',*,*,#288,.T.);
#1504=ORIENTED_EDGE('',*,*,#1493,.F.);
#1505=ORIENTED_EDGE('',*,*,#740,.F.);
#1506=DIRECTION('',(1.,0.,0.));
#1507=VECTOR('',#1506,1.);
#1508=CARTESIAN_POINT('',(0.60071,-2.82878067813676,-2.82878067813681));
#1509=LINE('',#1508,#1507);
#1510=EDGE_CURVE('E979',#731,#287,#1509,.T.);
#1511=ORIENTED_EDGE('',*,*,#1510,.T.);
#1512=EDGE_LOOP('',(#1503,#1504,#1505,#1511));
#1513=FACE_BOUND('',#1512,.T.);
#1514=ADVANCED_FACE('F626',(#1513),#1502,.F.);
#1515=CARTESIAN_POINT('',(0.60071,-2.82878067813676,-2.82878067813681));
#1516=DIRECTION('',(0.,0.984851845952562,0.173397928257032));
#1517=DIRECTION('',(0.,-0.173397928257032,0.984851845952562));
#1518=AXIS2_PLACEMENT_3D('',#1515,#1516,#1517);
#1519=PLANE('',#1518);
#1520=ORIENTED_EDGE('',*,*,#296,.T.);
#1521=ORIENTED_EDGE('',*,*,#1510,.F.);
#1522=ORIENTED_EDGE('',*,*,#732,.F.);
#1523=DIRECTION('',(1.,0.,0.));
#1524=VECTOR('',#1523,1.);
#1525=CARTESIAN_POINT('',(0.60071,-2.70594455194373,-3.52645559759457));
#1526=LINE('',#1525,#1524);
#1527=EDGE_CURVE('E974',#723,#295,#1526,.T.);
#1528=ORIENTED_EDGE('',*,*,#1527,.T.);
#1529=EDGE_LOOP('',(#1520,#1521,#1522,#1528));
#1530=FACE_BOUND('',#1529,.T.);
#1531=ADVANCED_FACE('F636',(#1530),#1519,.F.);
#1532=CARTESIAN_POINT('',(0.60071,-2.70594455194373,-3.52645559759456));
#1533=DIRECTION('',(0.,-0.0874088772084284,0.996172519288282));
#1534=DIRECTION('',(0.,-0.996172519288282,-0.0874088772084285));
#1535=AXIS2_PLACEMENT_3D('',#1532,#1533,#1534);
#1536=PLANE('',#1535);
#1537=ORIENTED_EDGE('',*,*,#304,.T.);
#1538=ORIENTED_EDGE('',*,*,#1527,.F.);
#1539=ORIENTED_EDGE('',*,*,#724,.F.);
#1540=DIRECTION('',(1.,0.,0.));
#1541=VECTOR('',#1540,1.);
#1542=CARTESIAN_POINT('',(0.60071,-2.00024999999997,-3.46453462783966));
#1543=LINE('',#1542,#1541);
#1544=EDGE_CURVE('E961',#715,#303,#1543,.T.);
#1545=ORIENTED_EDGE('',*,*,#1544,.T.);
#1546=EDGE_LOOP('',(#1537,#1538,#1539,#1545));
#1547=FACE_BOUND('',#1546,.T.);
#1548=ADVANCED_FACE('F646',(#1547),#1536,.F.);
#1549=CARTESIAN_POINT('',(0.60071,-2.00024999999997,-3.46453462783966));
#1550=DIRECTION('',(0.,0.906415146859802,0.422387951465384));
#1551=DIRECTION('',(0.,-0.422387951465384,0.906415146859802));
#1552=AXIS2_PLACEMENT_3D('',#1549,#1550,#1551);
#1553=PLANE('',#1552);
#1554=ORIENTED_EDGE('',*,*,#312,.T.);
#1555=ORIENTED_EDGE('',*,*,#1544,.F.);
#1556=ORIENTED_EDGE('',*,*,#716,.F.);
#1557=DIRECTION('',(1.,0.,0.));
#1558=VECTOR('',#1557,1.);
#1559=CARTESIAN_POINT('',(0.60071,-1.70102785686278,-4.10664452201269));
#1560=LINE('',#1559,#1558);
#1561=EDGE_CURVE('E956',#707,#311,#1560,.T.);
#1562=ORIENTED_EDGE('',*,*,#1561,.T.);
#1563=EDGE_LOOP('',(#1554,#1555,#1556,#1562));
#1564=FACE_BOUND('',#1563,.T.);
#1565=ADVANCED_FACE('F656',(#1564),#1553,.F.);
#1566=CARTESIAN_POINT('',(0.60071,-1.70102785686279,-4.10664452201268));
#1567=DIRECTION('',(0.,-0.342258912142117,0.939605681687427));
#1568=DIRECTION('',(0.,-0.939605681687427,-0.342258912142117));
#1569=AXIS2_PLACEMENT_3D('',#1566,#1567,#1568);
#1570=PLANE('',#1569);
#1571=ORIENTED_EDGE('',*,*,#320,.T.);
#1572=ORIENTED_EDGE('',*,*,#1561,.F.);
#1573=ORIENTED_EDGE('',*,*,#708,.F.);
#1574=DIRECTION('',(1.,0.,0.));
#1575=VECTOR('',#1574,1.);
#1576=CARTESIAN_POINT('',(0.60071,-1.0354055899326,-3.86418626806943));
#1577=LINE('',#1576,#1575);
#1578=EDGE_CURVE('E943',#699,#319,#1577,.T.);
#1579=ORIENTED_EDGE('',*,*,#1578,.T.);
#1580=EDGE_LOOP('',(#1571,#1572,#1573,#1579));
#1581=FACE_BOUND('',#1580,.T.);
#1582=ADVANCED_FACE('F666',(#1581),#1570,.F.);
#1583=CARTESIAN_POINT('',(0.60071,-1.0354055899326,-3.86418626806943));
#1584=DIRECTION('',(0.,0.7662077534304,0.642592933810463));
#1585=DIRECTION('',(0.,-0.642592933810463,0.7662077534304));
#1586=AXIS2_PLACEMENT_3D('',#1583,#1584,#1585);
#1587=PLANE('',#1586);
#1588=ORIENTED_EDGE('',*,*,#328,.T.);
#1589=ORIENTED_EDGE('',*,*,#1578,.F.);
#1590=ORIENTED_EDGE('',*,*,#700,.F.);
#1591=DIRECTION('',(1.,0.,0.));
#1592=VECTOR('',#1591,1.);
#1593=CARTESIAN_POINT('',(0.60071,-0.580188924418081,-4.40697240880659));
#1594=LINE('',#1593,#1592);
#1595=EDGE_CURVE('E938',#691,#327,#1594,.T.);
#1596=ORIENTED_EDGE('',*,*,#1595,.T.);
#1597=EDGE_LOOP('',(#1588,#1589,#1590,#1596));
#1598=FACE_BOUND('',#1597,.T.);
#1599=ADVANCED_FACE('F676',(#1598),#1587,.F.);
#1600=CARTESIAN_POINT('',(0.60071,-0.580188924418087,-4.40697240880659));
#1601=DIRECTION('',(0.,-0.573784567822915,0.819006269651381));
#1602=DIRECTION('',(0.,-0.819006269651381,-0.573784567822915));
#1603=AXIS2_PLACEMENT_3D('',#1600,#1601,#1602);
#1604=PLANE('',#1603);
#1605=ORIENTED_EDGE('',*,*,#336,.T.);
#1606=ORIENTED_EDGE('',*,*,#1595,.F.);
#1607=ORIENTED_EDGE('',*,*,#692,.F.);
#1608=DIRECTION('',(1.,0.,0.));
#1609=VECTOR('',#1608,1.);
#1610=CARTESIAN_POINT('',(0.60071,0.,-4.0005));
#1611=LINE('',#1610,#1609);
#1612=EDGE_CURVE('E925',#683,#335,#1611,.T.);
#1613=ORIENTED_EDGE('',*,*,#1612,.T.);
#1614=EDGE_LOOP('',(#1605,#1606,#1607,#1613));
#1615=FACE_BOUND('',#1614,.T.);
#1616=ADVANCED_FACE('F686',(#1615),#1604,.F.);
#1617=CARTESIAN_POINT('',(0.60071,0.,-4.0005));
#1618=DIRECTION('',(0.,0.573784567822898,0.819006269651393));
#1619=DIRECTION('',(0.,-0.819006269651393,0.573784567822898));
#1620=AXIS2_PLACEMENT_3D('',#1617,#1618,#1619);
#1621=PLANE('',#1620);
#1622=ORIENTED_EDGE('',*,*,#344,.T.);
#1623=ORIENTED_EDGE('',*,*,#1612,.F.);
#1624=ORIENTED_EDGE('',*,*,#684,.F.);
#1625=DIRECTION('',(1.,0.,0.));
#1626=VECTOR('',#1625,1.);
#1627=CARTESIAN_POINT('',(0.60071,0.58018892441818,-4.40697240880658));
#1628=LINE('',#1627,#1626);
#1629=EDGE_CURVE('E920',#675,#343,#1628,.T.);
#1630=ORIENTED_EDGE('',*,*,#1629,.T.);
#1631=EDGE_LOOP('',(#1622,#1623,#1624,#1630));
#1632=FACE_BOUND('',#1631,.T.);
#1633=ADVANCED_FACE('F696',(#1632),#1621,.F.);
#1634=CARTESIAN_POINT('',(0.60071,0.580188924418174,-4.40697240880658));
#1635=DIRECTION('',(0.,-0.766207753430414,0.642592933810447));
#1636=DIRECTION('',(0.,-0.642592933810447,-0.766207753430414));
#1637=AXIS2_PLACEMENT_3D('',#1634,#1635,#1636);
#1638=PLANE('',#1637);
#1639=ORIENTED_EDGE('',*,*,#352,.T.);
#1640=ORIENTED_EDGE('',*,*,#1629,.F.);
#1641=ORIENTED_EDGE('',*,*,#676,.F.);
#1642=DIRECTION('',(1.,0.,0.));
#1643=VECTOR('',#1642,1.);
#1644=CARTESIAN_POINT('',(0.60071,1.03540558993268,-3.86418626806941));
#1645=LINE('',#1644,#1643);
#1646=EDGE_CURVE('E907',#667,#351,#1645,.T.);
#1647=ORIENTED_EDGE('',*,*,#1646,.T.);
#1648=EDGE_LOOP('',(#1639,#1640,#1641,#1647));
#1649=FACE_BOUND('',#1648,.T.);
#1650=ADVANCED_FACE('F706',(#1649),#1638,.F.);
#1651=CARTESIAN_POINT('',(0.60071,1.03540558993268,-3.86418626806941));
#1652=DIRECTION('',(0.,0.342258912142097,0.939605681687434));
#1653=DIRECTION('',(0.,-0.939605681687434,0.342258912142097));
#1654=AXIS2_PLACEMENT_3D('',#1651,#1652,#1653);
#1655=PLANE('',#1654);
#1656=ORIENTED_EDGE('',*,*,#360,.T.);
#1657=ORIENTED_EDGE('',*,*,#1646,.F.);
#1658=ORIENTED_EDGE('',*,*,#668,.F.);
#1659=DIRECTION('',(1.,0.,0.));
#1660=VECTOR('',#1659,1.);
#1661=CARTESIAN_POINT('',(0.60071,1.70102785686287,-4.10664452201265));
#1662=LINE('',#1661,#1660);
#1663=EDGE_CURVE('E902',#659,#359,#1662,.T.);
#1664=ORIENTED_EDGE('',*,*,#1663,.T.);
#1665=EDGE_LOOP('',(#1656,#1657,#1658,#1664));
#1666=FACE_BOUND('',#1665,.T.);
#1667=ADVANCED_FACE('F716',(#1666),#1655,.F.);
#1668=CARTESIAN_POINT('',(0.60071,1.70102785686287,-4.10664452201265));
#1669=DIRECTION('',(0.,-0.906415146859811,0.422387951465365));
#1670=DIRECTION('',(0.,-0.422387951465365,-0.906415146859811));
#1671=AXIS2_PLACEMENT_3D('',#1668,#1669,#1670);
#1672=PLANE('',#1671);
#1673=ORIENTED_EDGE('',*,*,#368,.T.);
#1674=ORIENTED_EDGE('',*,*,#1663,.F.);
#1675=ORIENTED_EDGE('',*,*,#660,.F.);
#1676=DIRECTION('',(1.,0.,0.));
#1677=VECTOR('',#1676,1.);
#1678=CARTESIAN_POINT('',(0.60071,2.00025000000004,-3.46453462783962));
#1679=LINE('',#1678,#1677);
#1680=EDGE_CURVE('E889',#651,#367,#1679,.T.);
#1681=ORIENTED_EDGE('',*,*,#1680,.T.);
#1682=EDGE_LOOP('',(#1673,#1674,#1675,#1681));
#1683=FACE_BOUND('',#1682,.T.);
#1684=ADVANCED_FACE('F726',(#1683),#1672,.F.);
#1685=CARTESIAN_POINT('',(0.60071,2.00025000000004,-3.46453462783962));
#1686=DIRECTION('',(0.,0.0874088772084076,0.996172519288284));
#1687=DIRECTION('',(0.,-0.996172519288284,0.0874088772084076));
#1688=AXIS2_PLACEMENT_3D('',#1685,#1686,#1687);
#1689=PLANE('',#1688);
#1690=ORIENTED_EDGE('',*,*,#376,.T.);
#1691=ORIENTED_EDGE('',*,*,#1680,.F.);
#1692=ORIENTED_EDGE('',*,*,#652,.F.);
#1693=DIRECTION('',(1.,0.,0.));
#1694=VECTOR('',#1693,1.);
#1695=CARTESIAN_POINT('',(0.60071,2.70594455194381,-3.52645559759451));
#1696=LINE('',#1695,#1694);
#1697=EDGE_CURVE('E884',#643,#375,#1696,.T.);
#1698=ORIENTED_EDGE('',*,*,#1697,.T.);
#1699=EDGE_LOOP('',(#1690,#1691,#1692,#1698));
#1700=FACE_BOUND('',#1699,.T.);
#1701=ADVANCED_FACE('F736',(#1700),#1689,.F.);
#1702=CARTESIAN_POINT('',(0.60071,2.7059445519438,-3.52645559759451));
#1703=DIRECTION('',(0.,-0.984851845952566,0.173397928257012));
#1704=DIRECTION('',(0.,-0.173397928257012,-0.984851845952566));
#1705=AXIS2_PLACEMENT_3D('',#1702,#1703,#1704);
#1706=PLANE('',#1705);
#1707=ORIENTED_EDGE('',*,*,#384,.T.);
#1708=ORIENTED_EDGE('',*,*,#1697,.F.);
#1709=ORIENTED_EDGE('',*,*,#644,.F.);
#1710=DIRECTION('',(1.,0.,0.));
#1711=VECTOR('',#1710,1.);
#1712=CARTESIAN_POINT('',(0.60071,2.82878067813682,-2.82878067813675));
#1713=LINE('',#1712,#1711);
#1714=EDGE_CURVE('E871',#635,#383,#1713,.T.);
#1715=ORIENTED_EDGE('',*,*,#1714,.T.);
#1716=EDGE_LOOP('',(#1707,#1708,#1709,#1715));
#1717=FACE_BOUND('',#1716,.T.);
#1718=ADVANCED_FACE('F746',(#1717),#1706,.F.);
#1719=CARTESIAN_POINT('',(0.60071,2.82878067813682,-2.82878067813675));
#1720=DIRECTION('',(0.,-0.173397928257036,0.984851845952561));
#1721=DIRECTION('',(0.,-0.984851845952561,-0.173397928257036));
#1722=AXIS2_PLACEMENT_3D('',#1719,#1720,#1721);
#1723=PLANE('',#1722);
#1724=ORIENTED_EDGE('',*,*,#392,.T.);
#1725=ORIENTED_EDGE('',*,*,#1714,.F.);
#1726=ORIENTED_EDGE('',*,*,#636,.F.);
#1727=DIRECTION('',(1.,0.,0.));
#1728=VECTOR('',#1727,1.);
#1729=CARTESIAN_POINT('',(0.60071,3.52645559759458,-2.70594455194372));
#1730=LINE('',#1729,#1728);
#1731=EDGE_CURVE('E866',#627,#391,#1730,.T.);
#1732=ORIENTED_EDGE('',*,*,#1731,.T.);
#1733=EDGE_LOOP('',(#1724,#1725,#1726,#1732));
#1734=FACE_BOUND('',#1733,.T.);
#1735=ADVANCED_FACE('F756',(#1734),#1723,.F.);
#1736=CARTESIAN_POINT('',(0.60071,3.52645559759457,-2.70594455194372));
#1737=DIRECTION('',(0.,-0.996172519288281,-0.0874088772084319));
#1738=DIRECTION('',(0.,0.0874088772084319,-0.996172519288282));
#1739=AXIS2_PLACEMENT_3D('',#1736,#1737,#1738);
#1740=PLANE('',#1739);
#1741=ORIENTED_EDGE('',*,*,#400,.T.);
#1742=ORIENTED_EDGE('',*,*,#1731,.F.);
#1743=ORIENTED_EDGE('',*,*,#628,.F.);
#1744=DIRECTION('',(1.,0.,0.));
#1745=VECTOR('',#1744,1.);
#1746=CARTESIAN_POINT('',(0.60071,3.46453462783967,-2.00024999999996));
#1747=LINE('',#1746,#1745);
#1748=EDGE_CURVE('E854',#619,#399,#1747,.T.);
#1749=ORIENTED_EDGE('',*,*,#1748,.T.);
#1750=EDGE_LOOP('',(#1741,#1742,#1743,#1749));
#1751=FACE_BOUND('',#1750,.T.);
#1752=ADVANCED_FACE('F766',(#1751),#1740,.F.);
#1753=CARTESIAN_POINT('',(0.60071,3.46453462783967,-2.00024999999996));
#1754=DIRECTION('',(0.,-0.422387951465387,0.906415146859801));
#1755=DIRECTION('',(0.,-0.906415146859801,-0.422387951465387));
#1756=AXIS2_PLACEMENT_3D('',#1753,#1754,#1755);
#1757=PLANE('',#1756);
#1758=ORIENTED_EDGE('',*,*,#406,.T.);
#1759=ORIENTED_EDGE('',*,*,#1748,.F.);
#1760=ORIENTED_EDGE('',*,*,#620,.F.);
#1761=DIRECTION('',(1.,0.,0.));
#1762=VECTOR('',#1761,1.);
#1763=CARTESIAN_POINT('',(0.60071,4.10664452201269,-1.70102785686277));
#1764=LINE('',#1763,#1762);
#1765=EDGE_CURVE('E850',#611,#31,#1764,.T.);
#1766=ORIENTED_EDGE('',*,*,#1765,.T.);
#1767=EDGE_LOOP('',(#1758,#1759,#1760,#1766));
#1768=FACE_BOUND('',#1767,.T.);
#1769=ADVANCED_FACE('F776',(#1768),#1757,.F.);
#1770=CARTESIAN_POINT('',(0.60071,4.10664452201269,-1.70102785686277));
#1771=DIRECTION('',(0.,-0.939605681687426,-0.34225891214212));
#1772=DIRECTION('',(0.,0.34225891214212,-0.939605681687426));
#1773=AXIS2_PLACEMENT_3D('',#1770,#1771,#1772);
#1774=PLANE('',#1773);
#1775=ORIENTED_EDGE('',*,*,#32,.T.);
#1776=ORIENTED_EDGE('',*,*,#1765,.F.);
#1777=ORIENTED_EDGE('',*,*,#612,.F.);
#1778=DIRECTION('',(1.,0.,0.));
#1779=VECTOR('',#1778,1.);
#1780=CARTESIAN_POINT('',(0.60071,3.86418626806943,-1.03540558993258));
#1781=LINE('',#1780,#1779);
#1782=EDGE_CURVE('E818',#603,#29,#1781,.T.);
#1783=ORIENTED_EDGE('',*,*,#1782,.T.);
#1784=EDGE_LOOP('',(#1775,#1776,#1777,#1783));
#1785=FACE_BOUND('',#1784,.T.);
#1786=ADVANCED_FACE('F786',(#1785),#1774,.F.);
#1787=CARTESIAN_POINT('',(0.60071,3.86418626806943,-1.03540558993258));
#1788=DIRECTION('',(0.,-0.642592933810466,0.766207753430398));
#1789=DIRECTION('',(0.,-0.766207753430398,-0.642592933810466));
#1790=AXIS2_PLACEMENT_3D('',#1787,#1788,#1789);
#1791=PLANE('',#1790);
#1792=ORIENTED_EDGE('',*,*,#40,.T.);
#1793=ORIENTED_EDGE('',*,*,#1782,.F.);
#1794=ORIENTED_EDGE('',*,*,#604,.F.);
#1795=ORIENTED_EDGE('',*,*,#993,.T.);
#1796=EDGE_LOOP('',(#1792,#1793,#1794,#1795));
#1797=FACE_BOUND('',#1796,.T.);
#1798=ADVANCED_FACE('F796',(#1797),#1791,.F.);
#1799=CLOSED_SHELL('',(#421,#441,#461,#470,#487,#507,#527,#547,#567,#587,#982,#1004,#1021,#1038,
#1055,#1072,#1089,#1106,#1123,#1140,#1157,#1174,#1191,#1208,#1225,#1242,#1259,#1276,#1293,#1310,
#1327,#1344,#1361,#1378,#1395,#1412,#1429,#1446,#1463,#1480,#1497,#1514,#1531,#1548,#1565,#1582,
#1599,#1616,#1633,#1650,#1667,#1684,#1701,#1718,#1735,#1752,#1769,#1786,#1798));
#1800=MANIFOLD_SOLID_BREP('B2',#1799);
#1801=ADVANCED_BREP_SHAPE_REPRESENTATION('',(#18,#1800),#14);
#1802=SHAPE_DEFINITION_REPRESENTATION(#9,#1801);
ENDSEC;
END-ISO-10303-21;
